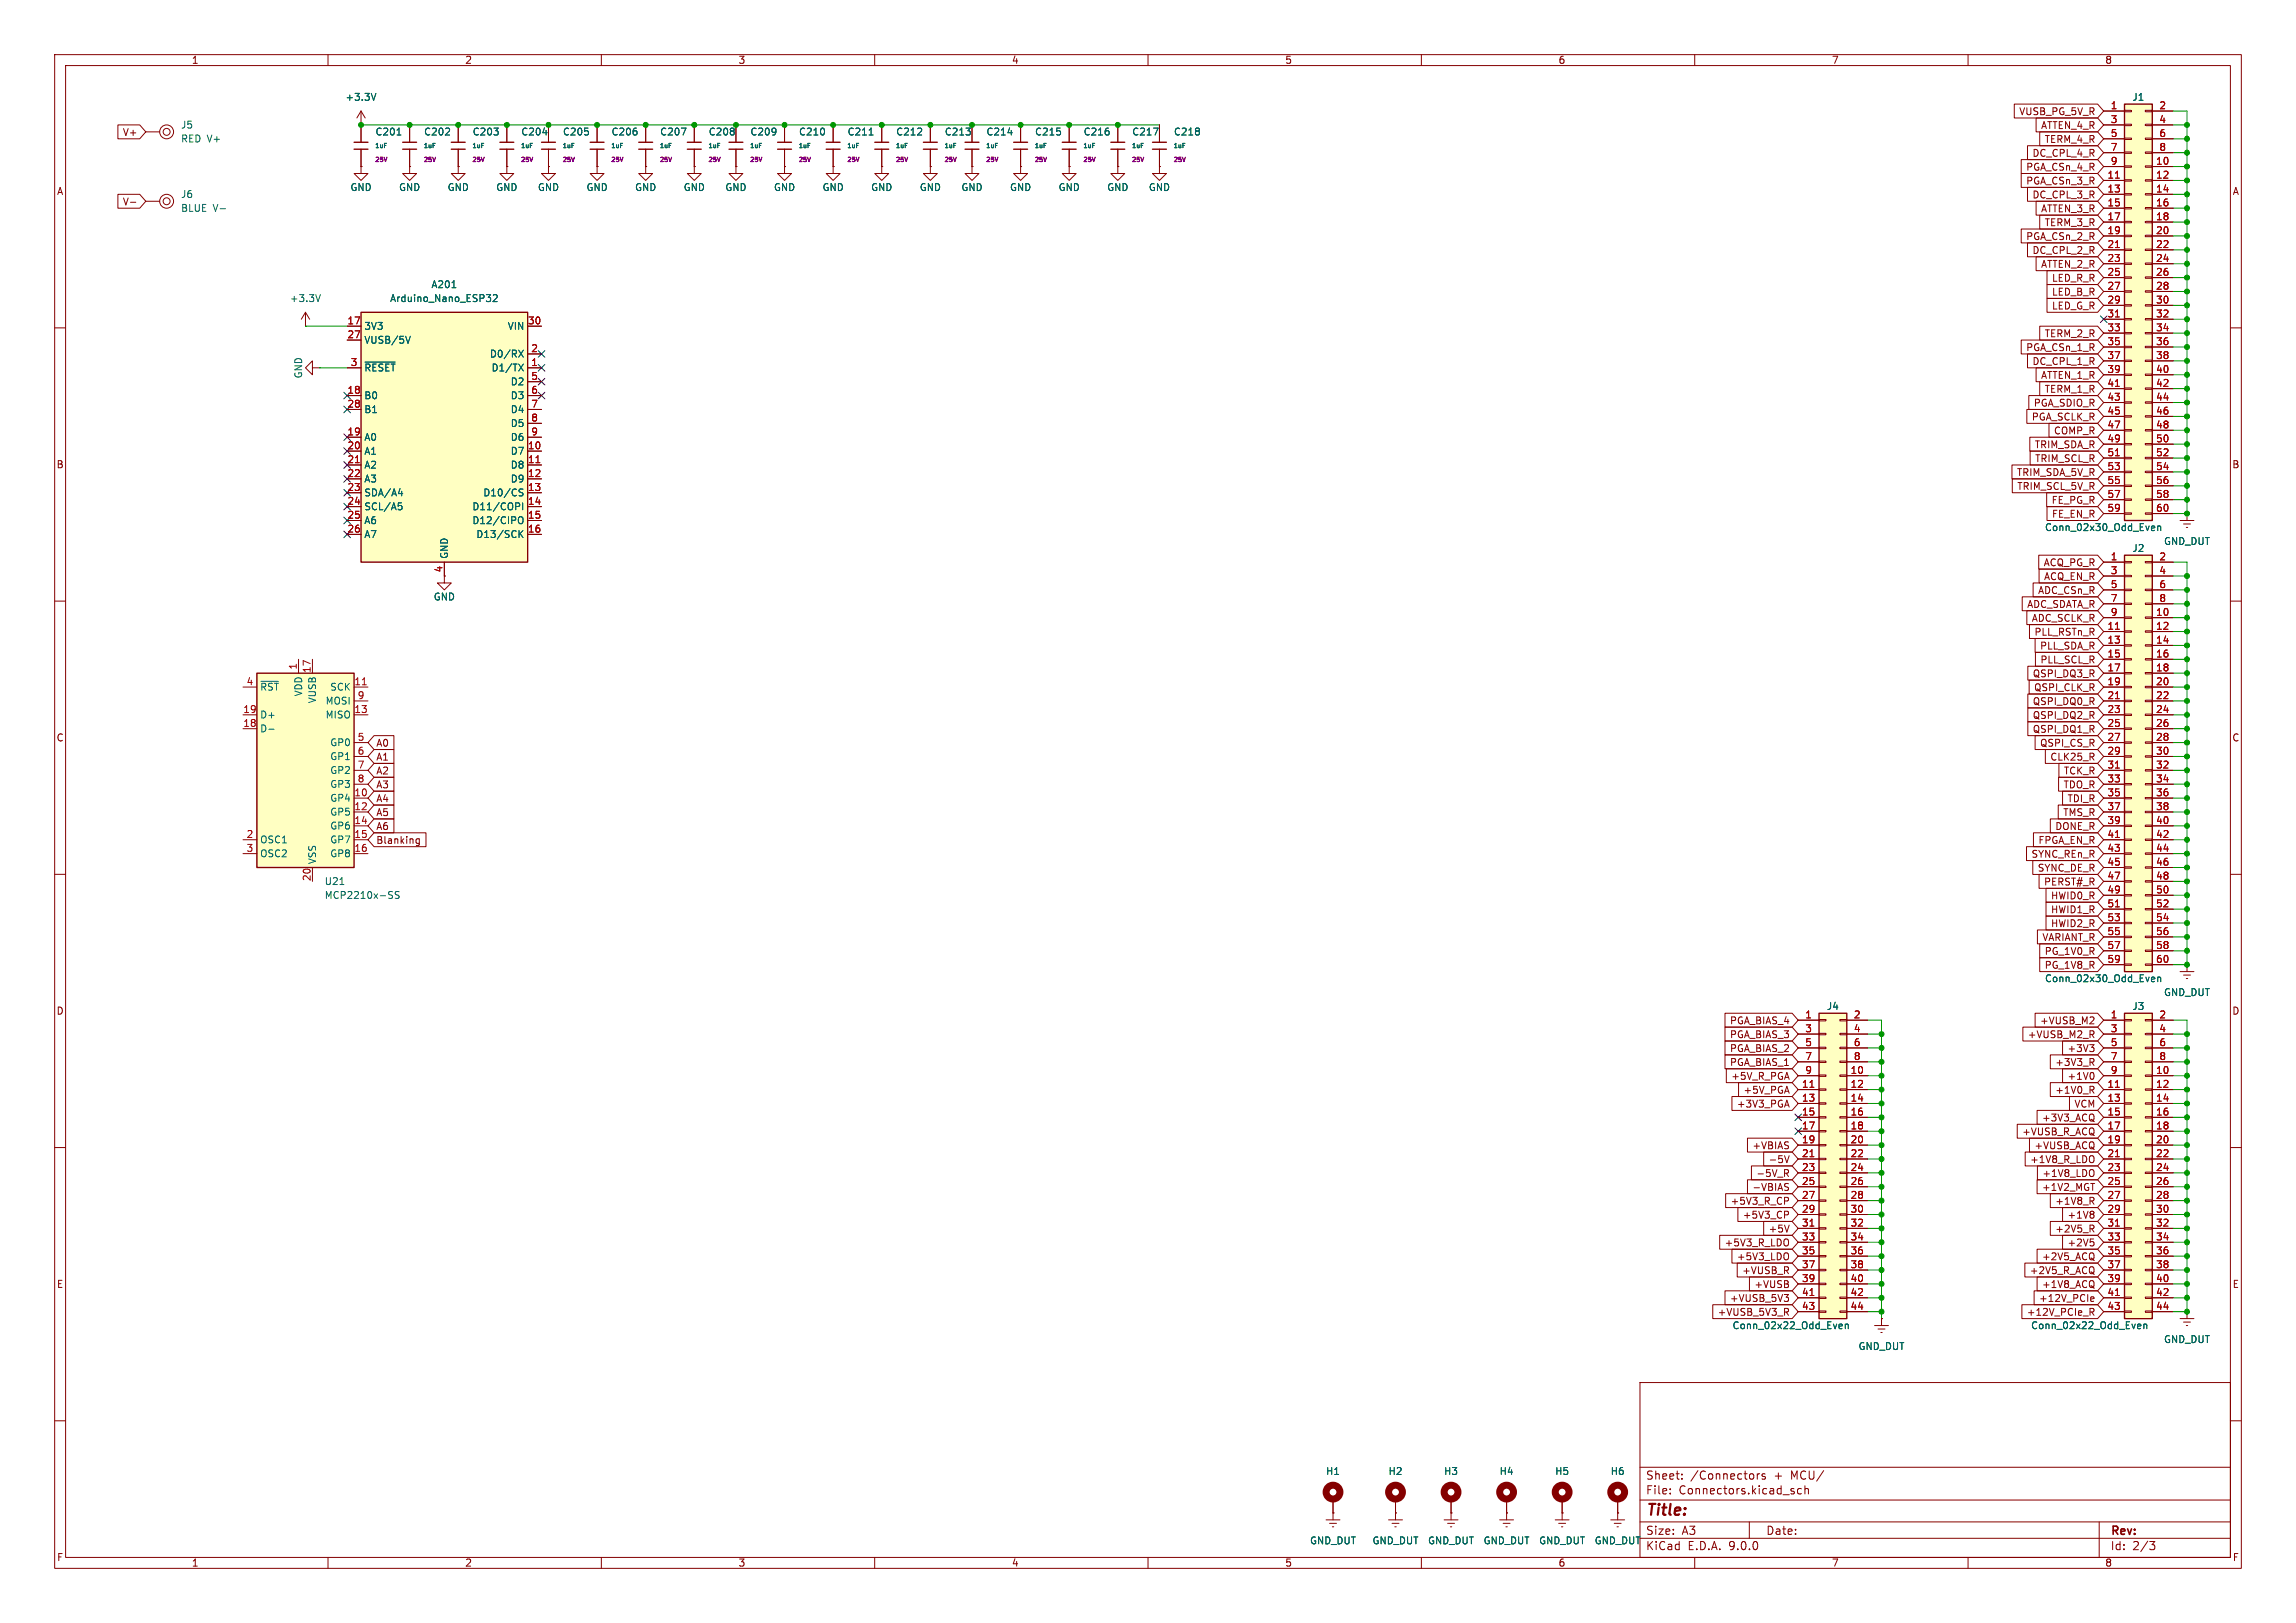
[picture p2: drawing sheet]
<svg xmlns="http://www.w3.org/2000/svg" width="420mm" height="297mm" viewBox="0 0 420 297" stroke-linecap="round" stroke-linejoin="round" font-family="sans-serif">
<defs><g id="words">
<text font-size="2.8" fill="#840000" x="301" y="277.9">Title:</text>
<g font-size="2.1" fill="#840000">
<text x="301" y="273.7">File:</text>
<text x="301" y="271">Sheet:</text>
<text x="307.1" y="273.7">Connectors.kicad_sch</text>
<text x="309.2" y="271">/Connectors</text>
<text x="324.6" y="271">+</text>
<text x="327.7" y="271">MCU/</text>
<text x="301" y="281.1">Size:</text>
<text x="307.6" y="281.1">A3</text>
<text x="323" y="281.1">Date:</text>
<text x="386" y="281.3">Rev:</text>
<text x="301" y="283.9">KiCad</text>
<text x="308.7" y="283.9">E.D.A.</text>
<text x="316.3" y="283.9">9.0.0</text>
<text x="386" y="283.9">Id:</text>
<text x="390.1" y="283.9">2/3</text>
</g>
<g font-size="1.8" fill="#840000">
<text x="35" y="11.9">1</text>
<text x="85" y="11.9">2</text>
<text x="135" y="11.9">3</text>
<text x="185" y="11.9">4</text>
<text x="235" y="11.9">5</text>
<text x="285" y="11.9">6</text>
<text x="335" y="11.9">7</text>
<text x="385" y="11.9">8</text>
<text x="369.3" y="21.3">VUSB_PG_5V_R</text>
<text x="373.3" y="23.8">ATTEN_4_R</text>
<text x="22.4" y="25.1">V+</text>
<text x="371.7" y="28.9">DC_CPL_4_R</text>
<text x="373.9" y="26.4">TERM_4_R</text>
<text x="10.3" y="35.9">A</text>
<text x="370.5" y="31.4">PGA_CSn_4_R</text>
<text x="370.5" y="34">PGA_CSn_3_R</text>
<text x="408.3" y="35.9">A</text>
<text x="22.4" y="37.8">V-</text>
<text x="371.7" y="36.5">DC_CPL_3_R</text>
<text x="373.3" y="39.1">ATTEN_3_R</text>
<text x="373.9" y="41.6">TERM_3_R</text>
<text x="370.5" y="44.1">PGA_CSn_2_R</text>
<text x="371.7" y="46.7">DC_CPL_2_R</text>
<text x="373.3" y="49.2">ATTEN_2_R</text>
<text x="375.3" y="51.8">LED_R_R</text>
<text x="375.3" y="56.8">LED_G_R</text>
<text x="375.3" y="54.3">LED_B_R</text>
<text x="370.5" y="64.5">PGA_CSn_1_R</text>
<text x="373.9" y="61.9">TERM_2_R</text>
<text x="371.7" y="67">DC_CPL_1_R</text>
<text x="373.3" y="69.5">ATTEN_1_R</text>
<text x="371.6" y="77.2">PGA_SCLK_R</text>
<text x="371.9" y="74.6">PGA_SDIO_R</text>
<text x="373.9" y="72.1">TERM_1_R</text>
<text x="372.1" y="82.2">TRIM_SDA_R</text>
<text x="375.6" y="79.7">COMP_R</text>
<text x="10.3" y="85.9">B</text>
<text x="368.8" y="87.3">TRIM_SDA_5V_R</text>
<text x="368.9" y="89.9">TRIM_SCL_5V_R</text>
<text x="372.2" y="84.8">TRIM_SCL_R</text>
<text x="408.2" y="85.9">B</text>
<text x="375.2" y="92.4">FE_PG_R</text>
<text x="375.3" y="94.9">FE_EN_R</text>
<text x="81" y="104.8" transform="rotate(-90 81 104.8)">4</text>
<text x="373.7" y="103.8">ACQ_PG_R</text>
<text x="373.8" y="106.4">ACQ_EN_R</text>
<text x="370.7" y="111.4">ADC_SDATA_R</text>
<text x="371.6" y="114">ADC_SCLK_R</text>
<text x="372.7" y="108.9">ADC_CSn_R</text>
<text x="372.1" y="116.5">PLL_RSTn_R</text>
<text x="373.1" y="119.1">PLL_SDA_R</text>
<text x="371.7" y="124.1">QSPI_DQ3_R</text>
<text x="373.1" y="121.6">PLL_SCL_R</text>
<text x="371.7" y="131.8">QSPI_DQ2_R</text>
<text x="371.7" y="129.2">QSPI_DQ0_R</text>
<text x="372" y="126.7">QSPI_CLK_R</text>
<text x="10.3" y="135.9">C</text>
<text x="68.7" y="136.8">A0</text>
<text x="371.7" y="134.3">QSPI_DQ1_R</text>
<text x="373.1" y="136.8">QSPI_CS_R</text>
<text x="408.2" y="135.9">C</text>
<text x="68.7" y="141.9">A2</text>
<text x="68.7" y="139.4">A1</text>
<text x="375" y="139.4">CLK25_R</text>
<text x="377.4" y="141.9">TCK_R</text>
<text x="68.7" y="144.5">A3</text>
<text x="68.7" y="147">A4</text>
<text x="68.7" y="149.5">A5</text>
<text x="377.3" y="149.5">TMS_R</text>
<text x="377.4" y="144.5">TDO_R</text>
<text x="378.1" y="147">TDI_R</text>
<text x="68.7" y="154.6">Blanking</text>
<text x="68.7" y="152.1">A6</text>
<text x="372.8" y="154.6">FPGA_EN_R</text>
<text x="375.9" y="152.1">DONE_R</text>
<text x="371.5" y="157.2">SYNC_REn_R</text>
<text x="372.7" y="159.7">SYNC_DE_R</text>
<text x="373.8" y="162.2">PERST#_R</text>
<text x="375.1" y="167.3">HWID1_R</text>
<text x="375.1" y="164.8">HWID0_R</text>
<text x="373.5" y="172.4">VARIANT_R</text>
<text x="375.1" y="169.9">HWID2_R</text>
<text x="373.9" y="174.9">PG_1V0_R</text>
<text x="373.9" y="177.5">PG_1V8_R</text>
<text x="10.3" y="185.9">D</text>
<text x="408.2" y="185.9">D</text>
<text x="316.4" y="187.6">PGA_BIAS_4</text>
<text x="316.4" y="190.2">PGA_BIAS_3</text>
<text x="370.8" y="190.2">+VUSB_M2_R</text>
<text x="373.1" y="187.6">+VUSB_M2</text>
<text x="316.4" y="192.7">PGA_BIAS_2</text>
<text x="316.4" y="195.3">PGA_BIAS_1</text>
<text x="316.6" y="197.8">+5V_R_PGA</text>
<text x="375.9" y="195.3">+3V3_R</text>
<text x="378.1" y="197.8">+1V0</text>
<text x="378.1" y="192.7">+3V3</text>
<text x="317.6" y="202.9">+3V3_PGA</text>
<text x="318.8" y="200.3">+5V_PGA</text>
<text x="375.9" y="200.3">+1V0_R</text>
<text x="379.4" y="202.9">VCM</text>
<text x="369.8" y="208">+VUSB_R_ACQ</text>
<text x="373.4" y="205.4">+3V3_ACQ</text>
<text x="320.5" y="210.5">+VBIAS</text>
<text x="321.2" y="215.6">-5V_R</text>
<text x="323.4" y="213">-5V</text>
<text x="371.3" y="213">+1V8_R_LDO</text>
<text x="372.1" y="210.5">+VUSB_ACQ</text>
<text x="373.5" y="215.6">+1V8_LDO</text>
<text x="316.5" y="220.7">+5V3_R_CP</text>
<text x="320.5" y="218.1">-VBIAS</text>
<text x="373.4" y="218.1">+1V2_MGT</text>
<text x="375.9" y="220.7">+1V8_R</text>
<text x="318.7" y="223.2">+5V3_CP</text>
<text x="323.4" y="225.7">+5V</text>
<text x="375.9" y="225.7">+2V5_R</text>
<text x="378.1" y="223.2">+1V8</text>
<text x="315.4" y="228.3">+5V3_R_LDO</text>
<text x="317.6" y="230.8">+5V3_LDO</text>
<text x="318.6" y="233.4">+VUSB_R</text>
<text x="371.2" y="233.4">+2V5_R_ACQ</text>
<text x="373.4" y="230.8">+2V5_ACQ</text>
<text x="378.1" y="228.3">+2V5</text>
<text x="10.3" y="235.9">E</text>
<text x="316.4" y="238.4">+VUSB_5V3</text>
<text x="320.8" y="235.9">+VUSB</text>
<text x="372.9" y="238.4">+12V_PCIe</text>
<text x="373.4" y="235.9">+1V8_ACQ</text>
<text x="408.3" y="235.9">E</text>
<text x="314.1" y="241">+VUSB_5V3_R</text>
<text x="370.7" y="241">+12V_PCIe_R</text>
<text x="10.3" y="285.9">F</text>
<text x="35" y="286.9">1</text>
<text x="85" y="286.9">2</text>
<text x="135" y="286.9">3</text>
<text x="185" y="286.9">4</text>
<text x="235" y="286.9">5</text>
<text x="285" y="286.9">6</text>
<text x="335" y="286.9">7</text>
<text x="385" y="286.9">8</text>
<text x="408.3" y="285.9">F</text>
</g>
<g font-size="1.8" fill="#006464">
<text x="33" y="23.7">J5</text>
<text x="63.1" y="18.6">+3.3V</text>
<text x="390" y="18.6">J1</text>
<text x="33" y="26.3">RED V+</text>
<text x="68.6" y="25">C201</text>
<text x="77.5" y="25">C202</text>
<text x="86.4" y="25">C203</text>
<text x="95.3" y="25">C204</text>
<text x="102.9" y="25">C205</text>
<text x="111.8" y="25">C206</text>
<text x="120.7" y="25">C207</text>
<text x="129.5" y="25">C208</text>
<text x="137.2" y="25">C209</text>
<text x="146.1" y="25">C210</text>
<text x="154.9" y="25">C211</text>
<text x="163.8" y="25">C212</text>
<text x="172.7" y="25">C213</text>
<text x="180.3" y="25">C214</text>
<text x="189.2" y="25">C215</text>
<text x="198.1" y="25">C216</text>
<text x="207" y="25">C217</text>
<text x="214.6" y="25">C218</text>
<text x="64" y="35.2">GND</text>
<text x="72.9" y="35.2">GND</text>
<text x="81.8" y="35.2">GND</text>
<text x="90.7" y="35.2">GND</text>
<text x="98.3" y="35.2">GND</text>
<text x="107.2" y="35.2">GND</text>
<text x="116.1" y="35.2">GND</text>
<text x="125" y="35.2">GND</text>
<text x="132.6" y="35.2">GND</text>
<text x="141.5" y="35.2">GND</text>
<text x="150.4" y="35.2">GND</text>
<text x="159.3" y="35.2">GND</text>
<text x="168.1" y="35.2">GND</text>
<text x="175.8" y="35.2">GND</text>
<text x="184.7" y="35.2">GND</text>
<text x="193.5" y="35.2">GND</text>
<text x="202.4" y="35.2">GND</text>
<text x="210.1" y="35.2">GND</text>
<text x="33" y="36.4">J6</text>
<text x="33" y="39">BLUE</text>
<text x="39" y="39">V-</text>
<text x="78.8" y="52.9">A201</text>
<text x="52.9" y="55.5">+3.3V</text>
<text x="71.3" y="55.5">Arduino_Nano_ESP32</text>
<text x="66.5" y="60.6">3V3</text>
<text x="66.5" y="63.1">VUSB/5V</text>
<text x="89.5" y="65.6">D0/RX</text>
<text x="92.8" y="60.6">VIN</text>
<text x="55.5" y="69.3" transform="rotate(-90 55.5 69.3)">GND</text>
<text x="66.5" y="68.2">~{RESET}</text>
<text x="89.8" y="68.2">D1/TX</text>
<text x="93.3" y="70.7">D2</text>
<text x="66.5" y="73.3">B0</text>
<text x="66.5" y="75.8">B1</text>
<text x="93.3" y="73.3">D3</text>
<text x="93.3" y="75.8">D4</text>
<text x="66.5" y="80.9">A0</text>
<text x="66.5" y="83.4">A1</text>
<text x="93.3" y="78.3">D5</text>
<text x="93.3" y="80.9">D6</text>
<text x="93.3" y="83.4">D7</text>
<text x="66.5" y="86">A2</text>
<text x="66.5" y="88.5">A3</text>
<text x="93.3" y="86">D8</text>
<text x="93.3" y="88.5">D9</text>
<text x="66.5" y="91">SDA/A4</text>
<text x="66.5" y="93.6">SCL/A5</text>
<text x="86.3" y="93.6">D11/COPI</text>
<text x="88.3" y="91">D10/CS</text>
<text x="66.5" y="96.1">A6</text>
<text x="66.5" y="98.7">A7</text>
<text x="86.3" y="96.1">D12/CIPO</text>
<text x="87" y="98.7">D13/SCK</text>
<text x="374" y="97.4">Conn_02x30_Odd_Even</text>
<text x="390" y="101.2">J2</text>
<text x="395.7" y="99.9">GND_DUT</text>
<text x="82.1" y="102.4" transform="rotate(-90 82.1 102.4)">GND</text>
<text x="79.2" y="110.1">GND</text>
<text x="47.5" y="126.6">~{RST}</text>
<text x="47.5" y="131.7">D+</text>
<text x="55.5" y="127.5" transform="rotate(-90 55.5 127.5)">VDD</text>
<text x="58" y="128.8" transform="rotate(-90 58 128.8)">VUSB</text>
<text x="59.5" y="129.1">MOSI</text>
<text x="59.5" y="131.7">MISO</text>
<text x="60.3" y="126.6">SCK</text>
<text x="47.5" y="134.2">D-</text>
<text x="60.3" y="136.8">GP0</text>
<text x="60.3" y="139.3">GP1</text>
<text x="60.3" y="141.8">GP2</text>
<text x="60.3" y="144.4">GP3</text>
<text x="60.3" y="146.9">GP4</text>
<text x="60.3" y="149.5">GP5</text>
<text x="47.5" y="154.5">OSC1</text>
<text x="60.3" y="152">GP6</text>
<text x="60.3" y="154.5">GP7</text>
<text x="47.5" y="157.1">OSC2</text>
<text x="58" y="158.2" transform="rotate(-90 58 158.2)">VSS</text>
<text x="60.3" y="157.1">GP8</text>
<text x="59.3" y="162.2">U21</text>
<text x="59.3" y="164.7">MCP2210x-SS</text>
<text x="374" y="179.9">Conn_02x30_Odd_Even</text>
<text x="334.1" y="185">J4</text>
<text x="390" y="185">J3</text>
<text x="395.7" y="182.5">GND_DUT</text>
<text x="316.8" y="243.4">Conn_02x22_Odd_Even</text>
<text x="371.4" y="243.4">Conn_02x22_Odd_Even</text>
<text x="395.7" y="246">GND_DUT</text>
<text x="339.9" y="247.2">GND_DUT</text>
<text x="242.5" y="270.1">H1</text>
<text x="253.9" y="270.1">H2</text>
<text x="264.1" y="270.1">H3</text>
<text x="274.2" y="270.1">H4</text>
<text x="284.4" y="270.1">H5</text>
<text x="294.5" y="270.1">H6</text>
<text x="239.5" y="282.8">GND_DUT</text>
<text x="251" y="282.8">GND_DUT</text>
<text x="261.1" y="282.8">GND_DUT</text>
<text x="271.3" y="282.8">GND_DUT</text>
<text x="281.4" y="282.8">GND_DUT</text>
<text x="291.6" y="282.8">GND_DUT</text>
</g>
<g font-size="1.8" fill="#a90000">
<text x="386" y="20.1">1</text>
<text x="386" y="22.6">3</text>
<text x="394.9" y="20.1">2</text>
<text x="394.9" y="22.6">4</text>
<text x="386" y="25.1">5</text>
<text x="386" y="27.7">7</text>
<text x="394.9" y="25.1">6</text>
<text x="394.9" y="27.7">8</text>
<text x="385.4" y="32.8">11</text>
<text x="385.4" y="35.3">13</text>
<text x="386" y="30.2">9</text>
<text x="394.3" y="30.2">10</text>
<text x="394.3" y="32.8">12</text>
<text x="394.3" y="35.3">14</text>
<text x="385.4" y="37.8">15</text>
<text x="385.4" y="40.4">17</text>
<text x="394.3" y="37.8">16</text>
<text x="394.3" y="40.4">18</text>
<text x="385.4" y="42.9">19</text>
<text x="385.4" y="45.5">21</text>
<text x="394.3" y="42.9">20</text>
<text x="394.3" y="45.5">22</text>
<text x="385.4" y="48">23</text>
<text x="385.4" y="50.5">25</text>
<text x="385.4" y="53.1">27</text>
<text x="394.3" y="48">24</text>
<text x="394.3" y="50.5">26</text>
<text x="394.3" y="53.1">28</text>
<text x="63.5" y="59.4">17</text>
<text x="96.5" y="59.4">30</text>
<text x="385.4" y="55.6">29</text>
<text x="385.4" y="58.2">31</text>
<text x="394.3" y="55.6">30</text>
<text x="394.3" y="58.2">32</text>
<text x="63.5" y="62">27</text>
<text x="97.1" y="64.5">2</text>
<text x="385.4" y="60.7">33</text>
<text x="385.4" y="63.2">35</text>
<text x="385.4" y="65.8">37</text>
<text x="394.3" y="60.7">34</text>
<text x="394.3" y="63.2">36</text>
<text x="394.3" y="65.8">38</text>
<text x="64.1" y="67.1">3</text>
<text x="97.1" y="67.1">1</text>
<text x="97.1" y="69.6">5</text>
<text x="385.4" y="68.3">39</text>
<text x="385.4" y="70.9">41</text>
<text x="394.3" y="68.3">40</text>
<text x="394.3" y="70.9">42</text>
<text x="63.5" y="72.1">18</text>
<text x="63.5" y="74.7">28</text>
<text x="97.1" y="72.1">6</text>
<text x="97.1" y="74.7">7</text>
<text x="97.1" y="77.2">8</text>
<text x="385.4" y="73.4">43</text>
<text x="385.4" y="75.9">45</text>
<text x="394.3" y="73.4">44</text>
<text x="394.3" y="75.9">46</text>
<text x="63.5" y="79.8">19</text>
<text x="63.5" y="82.3">20</text>
<text x="96.5" y="82.3">10</text>
<text x="97.1" y="79.8">9</text>
<text x="385.4" y="78.5">47</text>
<text x="385.4" y="81">49</text>
<text x="385.4" y="83.6">51</text>
<text x="394.3" y="78.5">48</text>
<text x="394.3" y="81">50</text>
<text x="394.3" y="83.6">52</text>
<text x="63.5" y="84.8">21</text>
<text x="63.5" y="87.4">22</text>
<text x="63.5" y="89.9">23</text>
<text x="96.5" y="84.8">11</text>
<text x="96.5" y="87.4">12</text>
<text x="96.5" y="89.9">13</text>
<text x="385.4" y="86.1">53</text>
<text x="385.4" y="88.6">55</text>
<text x="394.3" y="86.1">54</text>
<text x="394.3" y="88.6">56</text>
<text x="63.5" y="92.5">24</text>
<text x="63.5" y="95">25</text>
<text x="96.5" y="92.5">14</text>
<text x="96.5" y="95">15</text>
<text x="385.4" y="91.2">57</text>
<text x="385.4" y="93.7">59</text>
<text x="394.3" y="91.2">58</text>
<text x="394.3" y="93.7">60</text>
<text x="63.5" y="97.5">26</text>
<text x="96.5" y="97.5">16</text>
<text x="386" y="102.6">1</text>
<text x="386" y="105.2">3</text>
<text x="386" y="107.7">5</text>
<text x="394.9" y="102.6">2</text>
<text x="394.9" y="105.2">4</text>
<text x="394.9" y="107.7">6</text>
<text x="386" y="110.2">7</text>
<text x="386" y="112.8">9</text>
<text x="394.3" y="112.8">10</text>
<text x="394.9" y="110.2">8</text>
<text x="385.4" y="115.3">11</text>
<text x="385.4" y="117.9">13</text>
<text x="394.3" y="115.3">12</text>
<text x="394.3" y="117.9">14</text>
<text x="45" y="125.5">4</text>
<text x="54.4" y="122.6" transform="rotate(-90 54.4 122.6)">1</text>
<text x="56.9" y="123.2" transform="rotate(-90 56.9 123.2)">17</text>
<text x="64.7" y="125.5">11</text>
<text x="385.4" y="120.4">15</text>
<text x="385.4" y="122.9">17</text>
<text x="385.4" y="125.5">19</text>
<text x="394.3" y="120.4">16</text>
<text x="394.3" y="122.9">18</text>
<text x="394.3" y="125.5">20</text>
<text x="44.4" y="130.6">19</text>
<text x="64.7" y="130.6">13</text>
<text x="65.3" y="128">9</text>
<text x="385.4" y="128">21</text>
<text x="385.4" y="130.6">23</text>
<text x="394.3" y="128">22</text>
<text x="394.3" y="130.6">24</text>
<text x="44.4" y="133.1">18</text>
<text x="65.3" y="135.6">5</text>
<text x="385.4" y="133.1">25</text>
<text x="385.4" y="135.6">27</text>
<text x="394.3" y="133.1">26</text>
<text x="394.3" y="135.6">28</text>
<text x="65.3" y="138.2">6</text>
<text x="65.3" y="140.7">7</text>
<text x="65.3" y="143.3">8</text>
<text x="385.4" y="138.2">29</text>
<text x="385.4" y="140.7">31</text>
<text x="385.4" y="143.3">33</text>
<text x="394.3" y="138.2">30</text>
<text x="394.3" y="140.7">32</text>
<text x="394.3" y="143.3">34</text>
<text x="64.7" y="145.8">10</text>
<text x="64.7" y="148.3">12</text>
<text x="385.4" y="145.8">35</text>
<text x="385.4" y="148.3">37</text>
<text x="394.3" y="145.8">36</text>
<text x="394.3" y="148.3">38</text>
<text x="45" y="153.4">2</text>
<text x="45" y="156">3</text>
<text x="64.7" y="150.9">14</text>
<text x="64.7" y="153.4">15</text>
<text x="64.7" y="156">16</text>
<text x="385.4" y="150.9">39</text>
<text x="385.4" y="153.4">41</text>
<text x="385.4" y="156">43</text>
<text x="394.3" y="150.9">40</text>
<text x="394.3" y="153.4">42</text>
<text x="394.3" y="156">44</text>
<text x="56.9" y="161.3" transform="rotate(-90 56.9 161.3)">20</text>
<text x="385.4" y="158.5">45</text>
<text x="385.4" y="161">47</text>
<text x="394.3" y="158.5">46</text>
<text x="394.3" y="161">48</text>
<text x="385.4" y="163.6">49</text>
<text x="385.4" y="166.1">51</text>
<text x="394.3" y="163.6">50</text>
<text x="394.3" y="166.1">52</text>
<text x="385.4" y="168.7">53</text>
<text x="385.4" y="171.2">55</text>
<text x="385.4" y="173.7">57</text>
<text x="394.3" y="168.7">54</text>
<text x="394.3" y="171.2">56</text>
<text x="394.3" y="173.7">58</text>
<text x="385.4" y="176.3">59</text>
<text x="394.3" y="176.3">60</text>
<text x="330.1" y="186.4">1</text>
<text x="330.1" y="189">3</text>
<text x="330.1" y="191.5">5</text>
<text x="339" y="186.4">2</text>
<text x="339" y="189">4</text>
<text x="339" y="191.5">6</text>
<text x="386" y="186.4">1</text>
<text x="386" y="189">3</text>
<text x="386" y="191.5">5</text>
<text x="394.9" y="186.4">2</text>
<text x="394.9" y="189">4</text>
<text x="394.9" y="191.5">6</text>
<text x="330.1" y="194.1">7</text>
<text x="330.1" y="196.6">9</text>
<text x="338.4" y="196.6">10</text>
<text x="339" y="194.1">8</text>
<text x="386" y="194.1">7</text>
<text x="386" y="196.6">9</text>
<text x="394.3" y="196.6">10</text>
<text x="394.9" y="194.1">8</text>
<text x="329.5" y="199.1">11</text>
<text x="329.5" y="201.7">13</text>
<text x="338.4" y="199.1">12</text>
<text x="338.4" y="201.7">14</text>
<text x="385.4" y="199.1">11</text>
<text x="385.4" y="201.7">13</text>
<text x="394.3" y="199.1">12</text>
<text x="394.3" y="201.7">14</text>
<text x="329.5" y="204.2">15</text>
<text x="329.5" y="206.8">17</text>
<text x="329.5" y="209.3">19</text>
<text x="338.4" y="204.2">16</text>
<text x="338.4" y="206.8">18</text>
<text x="338.4" y="209.3">20</text>
<text x="385.4" y="204.2">15</text>
<text x="385.4" y="206.8">17</text>
<text x="385.4" y="209.3">19</text>
<text x="394.3" y="204.2">16</text>
<text x="394.3" y="206.8">18</text>
<text x="394.3" y="209.3">20</text>
<text x="329.5" y="211.8">21</text>
<text x="329.5" y="214.4">23</text>
<text x="338.4" y="211.8">22</text>
<text x="338.4" y="214.4">24</text>
<text x="385.4" y="211.8">21</text>
<text x="385.4" y="214.4">23</text>
<text x="394.3" y="211.8">22</text>
<text x="394.3" y="214.4">24</text>
<text x="329.5" y="216.9">25</text>
<text x="329.5" y="219.5">27</text>
<text x="329.5" y="222">29</text>
<text x="338.4" y="216.9">26</text>
<text x="338.4" y="219.5">28</text>
<text x="338.4" y="222">30</text>
<text x="385.4" y="216.9">25</text>
<text x="385.4" y="219.5">27</text>
<text x="385.4" y="222">29</text>
<text x="394.3" y="216.9">26</text>
<text x="394.3" y="219.5">28</text>
<text x="394.3" y="222">30</text>
<text x="329.5" y="224.5">31</text>
<text x="329.5" y="227.1">33</text>
<text x="338.4" y="224.5">32</text>
<text x="338.4" y="227.1">34</text>
<text x="385.4" y="224.5">31</text>
<text x="385.4" y="227.1">33</text>
<text x="394.3" y="224.5">32</text>
<text x="394.3" y="227.1">34</text>
<text x="329.5" y="229.6">35</text>
<text x="329.5" y="232.2">37</text>
<text x="338.4" y="229.6">36</text>
<text x="338.4" y="232.2">38</text>
<text x="385.4" y="229.6">35</text>
<text x="385.4" y="232.2">37</text>
<text x="394.3" y="229.6">36</text>
<text x="394.3" y="232.2">38</text>
<text x="329.5" y="234.7">39</text>
<text x="329.5" y="237.2">41</text>
<text x="329.5" y="239.8">43</text>
<text x="338.4" y="234.7">40</text>
<text x="338.4" y="237.2">42</text>
<text x="338.4" y="239.8">44</text>
<text x="385.4" y="234.7">39</text>
<text x="385.4" y="237.2">41</text>
<text x="385.4" y="239.8">43</text>
<text x="394.3" y="234.7">40</text>
<text x="394.3" y="237.2">42</text>
<text x="394.3" y="239.8">44</text>
</g>
<g font-size="1.1" fill="#840084">
<text x="68.5" y="29.8">25V</text>
<text x="77.4" y="29.8">25V</text>
<text x="86.3" y="29.8">25V</text>
<text x="95.2" y="29.8">25V</text>
<text x="102.8" y="29.8">25V</text>
<text x="111.7" y="29.8">25V</text>
<text x="120.6" y="29.8">25V</text>
<text x="129.5" y="29.8">25V</text>
<text x="137.1" y="29.8">25V</text>
<text x="146" y="29.8">25V</text>
<text x="154.9" y="29.8">25V</text>
<text x="163.8" y="29.8">25V</text>
<text x="172.6" y="29.8">25V</text>
<text x="180.3" y="29.8">25V</text>
<text x="189.2" y="29.8">25V</text>
<text x="198" y="29.8">25V</text>
<text x="206.9" y="29.8">25V</text>
<text x="214.6" y="29.8">25V</text>
</g>
<g font-size="1.1" fill="#006464">
<text x="68.5" y="27.3">1uF</text>
<text x="77.4" y="27.3">1uF</text>
<text x="86.3" y="27.3">1uF</text>
<text x="95.2" y="27.3">1uF</text>
<text x="102.8" y="27.3">1uF</text>
<text x="111.7" y="27.3">1uF</text>
<text x="120.6" y="27.3">1uF</text>
<text x="129.5" y="27.3">1uF</text>
<text x="137.1" y="27.3">1uF</text>
<text x="146" y="27.3">1uF</text>
<text x="154.9" y="27.3">1uF</text>
<text x="163.8" y="27.3">1uF</text>
<text x="172.6" y="27.3">1uF</text>
<text x="180.3" y="27.3">1uF</text>
<text x="189.2" y="27.3">1uF</text>
<text x="198" y="27.3">1uF</text>
<text x="206.9" y="27.3">1uF</text>
<text x="214.6" y="27.3">1uF</text>
</g>
</g></defs>
<g fill="none" stroke="#840000" stroke-width=".18">
<path d="M10 10h400v277h-400zM12 12h396v273h-396zM60 10v2M110 10v2M160 10v2M210 10v2M260 10v2M310 10v2M360 10v2M26.7 24.1h2.5M26.7 36.8h2.5M74.9 30.5v1.3h1.3l-1.3 1.2-1.2-1.2h1.2"/>
<path d="M74.9 30.5h.1M74.9 22.9v3.1M74.9 27.3v3.2M83.8 30.5v1.3h1.3l-1.3 1.2-1.3-1.2h1.3M83.8 30.5h.1M83.8 22.9v3.1M83.8 27.3v3.2M109.2 30.5v1.3h1.3l-1.3 1.2-1.3-1.2h1.3M109.2 30.5h.1M109.2 22.9v3.1M109.2 27.3v3.2M118.1 30.5v1.3h1.3l-1.3 1.2-1.3-1.2h1.3"/>
<path d="M118.1 30.5h.1M118.1 22.9v3.1M118.1 27.3v3.2M127 30.5v1.3h1.3l-1.3 1.2-1.3-1.2h1.3M127 30.5h.1M127 22.9v3.1M127 27.3v3.2M134.6 30.5v1.3h1.3l-1.3 1.2-1.3-1.2h1.3M134.6 30.5h.1M134.6 22.9v3.1M134.6 27.3v3.2M143.5 30.5v1.3h1.3l-1.3 1.2-1.3-1.2h1.3"/>
<path d="M143.5 30.5h.1M143.5 22.9v3.1M143.5 27.3v3.2M152.4 30.5v1.3h1.3l-1.3 1.2-1.3-1.2h1.3M152.4 30.5h.1M152.4 22.9v3.1M152.4 27.3v3.2M161.3 30.5v1.3h1.3l-1.3 1.2-1.3-1.2h1.3M161.3 30.5h.1M161.3 22.9v3.1M161.3 27.3v3.2M170.2 30.5v1.3h1.2l-1.2 1.2-1.3-1.2h1.3"/>
<path d="M170.2 30.5h.1M170.2 22.9v3.1M170.2 27.3v3.2M177.8 30.5v1.3h1.3l-1.3 1.2-1.3-1.2h1.3M177.8 30.5h.1M186.7 22.9v3.1M186.7 27.3v3.2M195.6 22.9v3.1M195.6 27.3v3.2M212.1 30.5v1.3h1.3l-1.3 1.2-1.3-1.2h1.3M212.1 30.5h.1M212.1 22.9v3.1"/>
<path d="M212.1 27.3v3.2M55.9 59.7h.1M55.9 57.2l.7 1.2M55.9 57.2l-.8 1.2M55.9 57.2v2.5M10 60h2M57.1 67.3v1.3l-1.2-1.3 1.2-1.3v1.3h1.3M58.4 67.3h.1M408 60h2M398.8 95.3h2.5M399.4 95.9h1.3M399.9 96.5h.3"/>
<path d="M400 94h.1M400 94v1.3M10 110h2M408 110h2M10 160h2M408 160h2M10 210h2M408 210h2M300 253h108v32h-108zM342.9 242.6h2.5M343.5 243.2h1.3M344 243.8h.3"/>
<path d="M344.2 241.3h.1M344.2 241.3v1.3M10 260h2M242.6 278.1h2.5M243.2 278.8h1.3M243.7 279.4h.3M243.8 276.9h.1M243.8 274.3v3.8M254 278.1h2.5M254.6 278.8h1.3M255.1 279.4h.3M255.3 276.9h.1"/>
<path d="M255.3 274.3v3.8M264.2 278.1h2.5M264.8 278.8h1.3M265.3 279.4h.3M265.4 276.9h.1M265.4 274.3v3.8M274.3 278.1h2.6M275 278.8h1.2M275.5 279.4h.2M275.6 276.9h.1M275.6 274.3v3.8M284.5 278.1h2.5"/>
<path d="M285.1 278.8h1.3M285.6 279.4h.3M285.7 276.9h.1M285.7 274.3v3.8M294.6 278.1h2.6M295.3 278.8h1.2M295.8 279.4h.2M295.9 276.9h.1M295.9 276.9v1.2M300 278.5h108M300 274.5h108M300 268.5h108"/>
<path d="M305.5 273.2v.2M305.5 272.5v.1M307.7 270.5v.2M307.7 269.8v.1M320 278.5v3M321.4 269.7v1M321.9 269.7l-.3 .1-.2 .2M322.9 269.8l-.4-.1-.2 .2 .1 .2 .5 .2v.3h-.6M328.2 273v.3M329.5 272.5l-.4-.1-.3 .3v.4l.1 .2h.6M330.2 272.5l.2-.1 .3 .1 .1 .9M330.2 271.9v1.5"/>
<path d="M384 278.5v6.5M408 260h2M60 285v2M110 285v2M160 285v2M210 285v2M260 285v2M300 281.5h108M310 285v2M360 285v2M393.2 282.1h1l-.5 .6 .4 .1 .1 .5-.3 .3h-.5"/>
<circle cx="30.5" cy="36.8" r=".63"/>
<circle cx="30.5" cy="24.1" r=".63"/>
<circle cx="30.5" cy="24.1" r="1.27"/>
<circle cx="30.5" cy="36.8" r="1.27"/>
</g>
<g fill="none" stroke="#840000" stroke-width="1.3">
<circle cx="243.8" cy="273" r="1.27"/>
<circle cx="255.3" cy="273" r="1.27"/>
<circle cx="265.4" cy="273" r="1.27"/>
<circle cx="275.6" cy="273" r="1.27"/>
<circle cx="285.8" cy="273" r="1.27"/>
</g>
<path d="M124.6 23.4h.9l-.6 1.3M159 24.7h.7M58.6 53.9l-.4 1.3" fill="none" stroke="#006464" stroke-width=".18"/>
<g fill="none" stroke="#840000" stroke-width=".25">
<path d="M73.7 26h2.5M73.7 27.3h2.5M82.5 26h2.6M82.5 27.3h2.6M107.9 26h2.6M107.9 27.3h2.6M116.8 26h2.6M116.8 27.3h2.6M125.7 26h2.6M125.7 27.3h2.6M133.3 26h2.6M133.3 27.3h2.6"/>
<path d="M142.2 26h2.6M142.2 27.3h2.6M151.1 26h2.6M151.1 27.3h2.6M160 26h2.6M160 27.3h2.6M168.9 26h2.5M168.9 27.3h2.5M185.4 26h2.6M185.4 27.3h2.6M194.3 26h2.5M194.3 27.3h2.5"/>
<path d="M210.8 26h2.6M210.8 27.3h2.6"/>
</g>
<path d="M332.7 185.4h5.1v55.9h-5.1z" fill="#ffffc2"/>
<path d="M332.7 185.4h5.1v55.9h-5.1z" fill="none" stroke="#840000" stroke-width=".25"/>
<g fill="none" stroke="#840000" stroke-width=".18">
<path d="M328.9 186.7h3.8M328.9 189.2h3.8M328.9 191.8h3.8M328.9 194.3h3.8M328.9 196.9h3.8M328.9 199.4h3.8M332.7 186.6h1.3v.2h-1.3zM332.7 189.1h1.3v.3h-1.3zM332.7 191.6h1.3v.3h-1.3zM332.7 194.2h1.3v.2h-1.3zM332.7 196.7h1.3v.3h-1.3zM332.7 199.3h1.3v.2h-1.3z"/>
<path d="M336.5 186.6h1.3v.2h-1.3zM336.5 189.1h1.3v.3h-1.3zM336.5 191.6h1.3v.3h-1.3zM336.5 194.2h1.3v.2h-1.3zM336.5 196.7h1.3v.3h-1.3zM336.5 199.3h1.3v.2h-1.3zM337.8 186.7h3.8M337.8 189.2h3.8M337.8 191.8h3.8M337.8 194.3h3.8M337.8 196.9h3.8M337.8 199.4h3.8"/>
<path d="M328.9 201.9h3.8M328.9 204.5h3.8M328.9 207h3.8M328.9 209.6h3.8M328.9 212.1h3.8M328.9 214.6h3.8M328.9 217.2h3.8M328.9 219.7h3.8M332.7 201.8h1.3v.3h-1.3zM332.7 204.3h1.3v.3h-1.3zM332.7 206.9h1.3v.2h-1.3zM332.7 209.4h1.3v.3h-1.3z"/>
<path d="M332.7 212h1.3v.2h-1.3zM332.7 214.5h1.3v.3h-1.3zM332.7 217h1.3v.3h-1.3zM332.7 219.6h1.3v.2h-1.3zM336.5 201.8h1.3v.3h-1.3zM336.5 204.3h1.3v.3h-1.3zM336.5 206.9h1.3v.2h-1.3zM336.5 209.4h1.3v.3h-1.3zM336.5 212h1.3v.2h-1.3zM336.5 214.5h1.3v.3h-1.3zM336.5 217h1.3v.3h-1.3zM336.5 219.6h1.3v.2h-1.3z"/>
<path d="M337.8 201.9h3.8M337.8 204.5h3.8M337.8 207h3.8M337.8 209.6h3.8M337.8 212.1h3.8M337.8 214.6h3.8M337.8 217.2h3.8M337.8 219.7h3.8M328.9 222.2h3.8M328.9 224.8h3.8M328.9 227.3h3.8M328.9 229.9h3.8"/>
<path d="M328.9 232.4h3.8M328.9 234.9h3.8M328.9 237.5h3.8M332.7 222.1h1.3v.3h-1.3zM332.7 224.7h1.3v.2h-1.3zM332.7 227.2h1.3v.3h-1.3zM332.7 229.7h1.3v.3h-1.3zM332.7 232.3h1.3v.2h-1.3zM332.7 234.8h1.3v.3h-1.3zM332.7 237.4h1.3v.2h-1.3zM332.7 239.9h1.3v.3h-1.3zM336.5 222.1h1.3v.3h-1.3z"/>
<path d="M336.5 224.7h1.3v.2h-1.3zM336.5 227.2h1.3v.3h-1.3zM336.5 229.7h1.3v.3h-1.3zM336.5 232.3h1.3v.2h-1.3zM336.5 234.8h1.3v.3h-1.3zM336.5 237.4h1.3v.2h-1.3zM336.5 239.9h1.3v.3h-1.3zM337.8 222.2h3.8M337.8 224.8h3.8M337.8 227.3h3.8M337.8 229.9h3.8M337.8 232.4h3.8"/>
<path d="M337.8 234.9h3.8M337.8 237.5h3.8M328.9 240h3.8M337.8 240h3.8"/>
</g>
<path d="M331.1 199h.7M331.1 211.7h.7M331.1 224.4h.7M331.1 237.1h.7" fill="none" stroke="#a90000" stroke-width=".18"/>
<path d="M336.6 242.3l.3 .1 .1 .2-.6 .1M336.9 243.1h-.3M337.5 242.4l.2-.1 .3 .1 .1 .7M337.5 242.3v.8" fill="none" stroke="#006464" stroke-width=".18"/>
<path d="M388.6 19.1h5.1v76.2h-5.1z" fill="#ffffc2"/>
<path d="M388.6 19.1h5.1v76.2h-5.1zM64.8 26h2.5M64.8 27.3h2.5M176.5 26h2.6M176.5 27.3h2.6M203.2 26h2.5M203.2 27.3h2.5" fill="none" stroke="#840000" stroke-width=".25"/>
<g fill="none" stroke="#840000" stroke-width=".18">
<path d="M66 30.5v1.3h1.3l-1.3 1.2-1.2-1.2h1.2M66 30.5h.1M66 22.9h.1M66 20.3v5.7M66 27.3v3.2M66 20.3l-.7 1.3M66 20.3l.8 1.3M177.8 22.9v3.1M177.8 27.3v3.2M186.7 30.5v1.3h1.3l-1.3 1.2-1.3-1.2h1.3M186.7 30.5h.1M195.6 30.5v1.3h1.2l-1.2 1.2-1.3-1.2h1.3"/>
<path d="M195.6 30.5h.1M204.5 30.5v1.3h1.2l-1.2 1.2-1.3-1.2h1.3M204.5 30.5h.1M204.5 22.9v3.1M204.5 27.3v3.2M384.8 20.3h3.8M384.8 22.9h3.8M384.8 25.4h3.8M384.8 27.9h3.8M384.8 30.5h3.8M384.8 33h3.8M384.8 35.6h3.8"/>
<path d="M384.8 38.1h3.8M388.6 20.2h1.3v.2h-1.3zM388.6 22.7h1.3v.3h-1.3zM388.6 25.3h1.3v.2h-1.3zM388.6 27.8h1.3v.3h-1.3zM388.6 30.4h1.3v.2h-1.3zM388.6 32.9h1.3v.2h-1.3zM388.6 35.4h1.3v.3h-1.3zM388.6 38h1.3v.2h-1.3zM392.4 20.2h1.3v.2h-1.3zM392.4 22.7h1.3v.3h-1.3zM392.4 25.3h1.3v.2h-1.3z"/>
<path d="M392.4 27.8h1.3v.3h-1.3zM392.4 30.4h1.3v.2h-1.3zM392.4 32.9h1.3v.2h-1.3zM392.4 35.4h1.3v.3h-1.3zM392.4 38h1.3v.2h-1.3zM393.7 20.3h3.8M393.7 22.9h3.8M393.7 25.4h3.8M393.7 27.9h3.8M393.7 30.5h3.8M393.7 33h3.8M393.7 35.6h3.8"/>
<path d="M393.7 38.1h3.8M384.8 40.6h3.8M384.8 43.2h3.8M384.8 45.7h3.8M384.8 48.3h3.8M384.8 50.8h3.8M384.8 53.3h3.8M384.8 55.9h3.8M384.8 58.4h3.8M388.6 40.5h1.3v.3h-1.3zM388.6 43.1h1.3v.2h-1.3zM388.6 45.6h1.3v.2h-1.3z"/>
<path d="M388.6 48.1h1.3v.3h-1.3zM388.6 50.7h1.3v.2h-1.3zM388.6 53.2h1.3v.3h-1.3zM388.6 55.8h1.3v.2h-1.3zM388.6 58.3h1.3v.2h-1.3zM392.4 40.5h1.3v.3h-1.3zM392.4 43.1h1.3v.2h-1.3zM392.4 45.6h1.3v.2h-1.3zM392.4 48.1h1.3v.3h-1.3zM392.4 50.7h1.3v.2h-1.3zM392.4 53.2h1.3v.3h-1.3zM392.4 55.8h1.3v.2h-1.3z"/>
<path d="M392.4 58.3h1.3v.2h-1.3zM393.7 40.6h3.8M393.7 43.2h3.8M393.7 45.7h3.8M393.7 48.3h3.8M393.7 50.8h3.8M393.7 53.3h3.8M393.7 55.9h3.8M393.7 58.4h3.8M384.8 61h3.8M384.8 63.5h3.8M384.8 66h3.8"/>
<path d="M384.8 68.6h3.8M384.8 71.1h3.8M384.8 73.7h3.8M384.8 76.2h3.8M384.8 78.7h3.8M388.6 60.8h1.3v.3h-1.3zM388.6 63.4h1.3v.2h-1.3zM388.6 65.9h1.3v.3h-1.3zM388.6 68.5h1.3v.2h-1.3zM388.6 71h1.3v.2h-1.3zM388.6 73.5h1.3v.3h-1.3zM388.6 76.1h1.3v.2h-1.3z"/>
<path d="M388.6 78.6h1.3v.3h-1.3zM392.4 60.8h1.3v.3h-1.3zM392.4 63.4h1.3v.2h-1.3zM392.4 65.9h1.3v.3h-1.3zM392.4 68.5h1.3v.2h-1.3zM392.4 71h1.3v.2h-1.3zM392.4 73.5h1.3v.3h-1.3zM392.4 76.1h1.3v.2h-1.3zM392.4 78.6h1.3v.3h-1.3zM393.7 61h3.8M393.7 63.5h3.8M393.7 66h3.8"/>
<path d="M393.7 68.6h3.8M393.7 71.1h3.8M393.7 73.7h3.8M393.7 76.2h3.8M393.7 78.7h3.8M384.8 81.3h3.8M384.8 83.8h3.8M384.8 86.4h3.8M384.8 88.9h3.8M384.8 91.4h3.8M384.8 94h3.8M388.6 81.2h1.3v.2h-1.3z"/>
<path d="M388.6 83.7h1.3v.2h-1.3zM388.6 86.2h1.3v.3h-1.3zM388.6 88.8h1.3v.2h-1.3zM388.6 91.3h1.3v.3h-1.3zM388.6 93.9h1.3v.2h-1.3zM392.4 81.2h1.3v.2h-1.3zM392.4 83.7h1.3v.2h-1.3zM392.4 86.2h1.3v.3h-1.3zM392.4 88.8h1.3v.2h-1.3zM392.4 91.3h1.3v.3h-1.3zM392.4 93.9h1.3v.2h-1.3zM393.7 81.3h3.8"/>
<path d="M393.7 83.8h3.8M393.7 86.4h3.8M393.7 88.9h3.8M393.7 91.4h3.8M393.7 94h3.8M81.3 105.4v1.3h-1.3l1.3 1.3 1.2-1.3h-1.2M398.8 177.8h2.5M399.4 178.4h1.3M399.9 179.1h.3M400 176.5h.1M400 176.5v1.3"/>
</g>
<path d="M387 32.6h.7M387 45.3h.7M387 58h.7M387 70.7h.7M387 83.4h.7" fill="none" stroke="#a90000" stroke-width=".18"/>
<path d="M68.8 17.1l-.5 1.3M72.6 24.7h.7M184.4 24.3h.8M211 23.4h.8l-.5 1.3M393.7 96.3h.4l.1 .3-.7 .1M394.1 97l-.4 .1M394.7 96.4l.2-.1h.3v.8M394.7 96.3v.8" fill="none" stroke="#006464" stroke-width=".18"/>
<path d="M66 57.2h30.5v45.7h-30.5z" fill="#ffffc2"/>
<path d="M66 57.2h30.5v45.7h-30.5z" fill="none" stroke="#840000" stroke-width=".25"/>
<g fill="none" stroke="#840000" stroke-width=".18">
<path d="M63.5 59.7h2.5M96.5 59.7h2.6M63.5 67.3h2.5M63.5 72.4h2.5M63.5 74.9h2.5M63.5 62.2h2.5M96.5 64.8h2.6M96.5 67.3h2.6M96.5 69.9h2.6M96.5 72.4h2.6M96.5 74.9h2.6M96.5 77.5h2.6"/>
<path d="M63.5 80h2.5M63.5 82.6h2.5M63.5 85.1h2.5M63.5 87.6h2.5M63.5 90.2h2.5M63.5 92.7h2.5M63.5 95.3h2.5M63.5 97.8h2.5M96.5 80h2.6M96.5 82.6h2.6M96.5 85.1h2.6M96.5 87.6h2.6"/>
<path d="M96.5 90.2h2.6M96.5 92.7h2.6M96.5 95.3h2.6M96.5 97.8h2.6M81.3 102.9v2.5"/>
</g>
<g fill="none" stroke="#006464" stroke-width=".18">
<path d="M82.7 52.6h.7M89 53.9h.7l-.4 .5M89.5 54.4l.2 .2v.3l-.2 .3M90.2 54l.5-.1 .3 .4-.8 .9h.8M66.8 66.3h5.5M74.2 61.5l.4 1.3 .5-1.3M94.9 64.1l.8 1.2M94.9 66.6l.8 1.3M95.7 64.1l-.8 1.2M95.7 66.6l-.8 1.3M72.9 92h.6M72.9 90.3h.8"/>
<path d="M73 92.5h.3l.2 .2v.5l-.5 .1M73.5 89.9v.8M94.8 92l.3 .3-.1 .3-.2 .1M94.9 94.7l.2-.1a.43 .43 0 0 1 .6 .4v.4a.43 .43 0 0 1-.3 .4 .43 .43 0 0 1-.5-.2M95 90l.5 .2 .2 .3-.3 .2h-.5M95.1 97.6l.6 .8M95.6 92v1.3M95.7 97.1l-.8 .7M95.7 89.5h-.5l-.2 .1"/>
</g>
<path d="M65 84.7h.7M98 84.7h.8" fill="none" stroke="#a90000" stroke-width=".18"/>
<path d="M47 123.2h17.8v35.6h-17.8z" fill="#ffffc2"/>
<path d="M91.4 26h2.6M91.4 27.3h2.6M99.1 26h2.5M99.1 27.3h2.5M47 123.2h17.8v35.6h-17.8z" fill="none" stroke="#840000" stroke-width=".25"/>
<g fill="none" stroke="#840000" stroke-width=".18">
<path d="M92.7 30.5v1.3h1.3l-1.3 1.2-1.3-1.2h1.3M92.7 30.5h.1M92.7 22.9v3.1M92.7 27.3v3.2M100.3 30.5v1.3h1.3l-1.3 1.2-1.2-1.2h1.2M100.3 30.5h.1M100.3 22.9v3.1M100.3 27.3v3.2M44.4 125.7h2.6M44.4 130.8h2.6M44.4 133.4h2.6M54.6 120.7v2.5"/>
<path d="M57.1 120.7v2.5M64.8 125.7h2.5M64.8 130.8h2.5M64.8 128.3h2.5M64.8 135.9h2.5M64.8 138.4h2.5M44.4 153.7h2.6M44.4 156.2h2.6M57.1 158.8v2.5M64.8 153.7h2.5M64.8 156.2h2.5M64.8 141h2.5"/>
<path d="M64.8 143.5h2.5M64.8 146.1h2.5M64.8 148.6h2.5M64.8 151.1h2.5M398.8 241.3h2.5M399.4 241.9h1.3M399.9 242.6h.3M400 240h.1M400 240v1.3"/>
</g>
<path d="M99.3 24.3h.8M47.7 124.7h3.2M49.2 133.4h.9M62.2 161.9h.7M71.3 163.7l.4 .2 .1 .3-.2 .2h-.3M71.3 163.1l.5 .1M73 163.2l-.5-.1-.2 .2v.3l.6 .3 .1 .3-.2 .2-.5-.1" fill="none" stroke="#006464" stroke-width=".18"/>
<path d="M66.3 125.3h.7" fill="none" stroke="#a90000" stroke-width=".18"/>
<path d="M388.6 101.6h5.1v76.2h-5.1z" fill="#ffffc2"/>
<path d="M388.6 101.6h5.1v76.2h-5.1z" fill="none" stroke="#840000" stroke-width=".25"/>
<g fill="none" stroke="#840000" stroke-width=".18">
<path d="M384.8 102.9h3.8M384.8 105.4h3.8M384.8 108h3.8M384.8 110.5h3.8M384.8 113h3.8M384.8 115.6h3.8M384.8 118.1h3.8M388.6 102.7h1.3v.3h-1.3zM388.6 105.3h1.3v.2h-1.3zM388.6 107.8h1.3v.3h-1.3zM388.6 110.4h1.3v.2h-1.3zM388.6 112.9h1.3v.3h-1.3z"/>
<path d="M388.6 115.4h1.3v.3h-1.3zM388.6 118h1.3v.2h-1.3zM392.4 102.7h1.3v.3h-1.3zM392.4 105.3h1.3v.2h-1.3zM392.4 107.8h1.3v.3h-1.3zM392.4 110.4h1.3v.2h-1.3zM392.4 112.9h1.3v.3h-1.3zM392.4 115.4h1.3v.3h-1.3zM392.4 118h1.3v.2h-1.3zM393.7 102.9h3.8M393.7 105.4h3.8M393.7 108h3.8"/>
<path d="M393.7 110.5h3.8M393.7 113h3.8M393.7 115.6h3.8M393.7 118.1h3.8M384.8 120.7h3.8M384.8 123.2h3.8M384.8 125.7h3.8M384.8 128.3h3.8M384.8 130.8h3.8M384.8 133.4h3.8M384.8 135.9h3.8M384.8 138.4h3.8"/>
<path d="M388.6 120.5h1.3v.3h-1.3zM388.6 123.1h1.3v.2h-1.3zM388.6 125.6h1.3v.3h-1.3zM388.6 128.1h1.3v.3h-1.3zM388.6 130.7h1.3v.2h-1.3zM388.6 133.2h1.3v.3h-1.3zM388.6 135.8h1.3v.2h-1.3zM388.6 138.3h1.3v.3h-1.3zM392.4 120.5h1.3v.3h-1.3zM392.4 123.1h1.3v.2h-1.3zM392.4 125.6h1.3v.3h-1.3zM392.4 128.1h1.3v.3h-1.3z"/>
<path d="M392.4 130.7h1.3v.2h-1.3zM392.4 133.2h1.3v.3h-1.3zM392.4 135.8h1.3v.2h-1.3zM392.4 138.3h1.3v.3h-1.3zM393.7 120.7h3.8M393.7 123.2h3.8M393.7 125.7h3.8M393.7 128.3h3.8M393.7 130.8h3.8M393.7 133.4h3.8M393.7 135.9h3.8M393.7 138.4h3.8"/>
<path d="M384.8 141h3.8M384.8 143.5h3.8M384.8 146.1h3.8M384.8 148.6h3.8M384.8 151.1h3.8M384.8 153.7h3.8M384.8 156.2h3.8M384.8 158.8h3.8M388.6 140.8h1.3v.3h-1.3zM388.6 143.4h1.3v.2h-1.3zM388.6 145.9h1.3v.3h-1.3zM388.6 148.5h1.3v.2h-1.3z"/>
<path d="M388.6 151h1.3v.3h-1.3zM388.6 153.5h1.3v.3h-1.3zM388.6 156.1h1.3v.2h-1.3zM388.6 158.6h1.3v.3h-1.3zM392.4 140.8h1.3v.3h-1.3zM392.4 143.4h1.3v.2h-1.3zM392.4 145.9h1.3v.3h-1.3zM392.4 148.5h1.3v.2h-1.3zM392.4 151h1.3v.3h-1.3zM392.4 153.5h1.3v.3h-1.3zM392.4 156.1h1.3v.2h-1.3zM392.4 158.6h1.3v.3h-1.3z"/>
<path d="M393.7 141h3.8M393.7 143.5h3.8M393.7 146.1h3.8M393.7 148.6h3.8M393.7 151.1h3.8M393.7 153.7h3.8M393.7 156.2h3.8M393.7 158.8h3.8M384.8 161.3h3.8M384.8 163.8h3.8M384.8 166.4h3.8M384.8 168.9h3.8"/>
<path d="M384.8 171.5h3.8M384.8 174h3.8M384.8 176.5h3.8M388.6 161.2h1.3v.2h-1.3zM388.6 163.7h1.3v.3h-1.3zM388.6 166.2h1.3v.3h-1.3zM388.6 168.8h1.3v.2h-1.3zM388.6 171.3h1.3v.3h-1.3zM388.6 173.9h1.3v.2h-1.3zM388.6 176.4h1.3v.3h-1.3zM392.4 161.2h1.3v.2h-1.3zM392.4 163.7h1.3v.3h-1.3z"/>
<path d="M392.4 166.2h1.3v.3h-1.3zM392.4 168.8h1.3v.2h-1.3zM392.4 171.3h1.3v.3h-1.3zM392.4 173.9h1.3v.2h-1.3zM392.4 176.4h1.3v.3h-1.3zM393.7 161.3h3.8M393.7 163.8h3.8M393.7 166.4h3.8M393.7 168.9h3.8M393.7 171.5h3.8M393.7 174h3.8M393.7 176.5h3.8"/>
</g>
<path d="M387 115.2h.7M387 127.9h.7M387 140.6h.7M387 153.3h.7M387 166h.7" fill="none" stroke="#a90000" stroke-width=".18"/>
<path d="M393.7 178.8l.4 .1 .1 .2-.7 .1M394.1 179.6h-.4M394.7 178.9l.2-.1 .3 .1v.7M394.7 178.8v.8" fill="none" stroke="#006464" stroke-width=".18"/>
<path d="M388.6 185.4h5.1v55.9h-5.1z" fill="#ffffc2"/>
<path d="M388.6 185.4h5.1v55.9h-5.1z" fill="none" stroke="#840000" stroke-width=".25"/>
<g fill="none" stroke="#840000" stroke-width=".18">
<path d="M368.5 19h15.2l1.1 1.3-1.1 1.3h-15.2zM21.6 22.9h4l1.1 1.2-1.1 1.3h-4zM21.6 35.6h4l1.1 1.2-1.1 1.3h-4zM23.9 37h.9M66 30.5h.1M66 22.9h.1M66 22.9v3.1M66 27.3v3.2M74.9 30.5h.1M74.9 22.9v3.1M74.9 27.3v3.2M83.8 30.5h.1"/>
<path d="M83.8 22.9v3.1M83.8 27.3v3.2M92.7 30.5h.1M92.7 22.9v3.1M92.7 27.3v3.2M100.3 30.5h.1M100.3 22.9v3.1M100.3 27.3v3.2M109.2 30.5h.1M109.2 22.9v3.1M109.2 27.3v3.2M118.1 30.5h.1"/>
<path d="M118.1 22.9v3.1M118.1 27.3v3.2M127 30.5h.1M127 22.9v3.1M127 27.3v3.2M134.6 30.5h.1M134.6 22.9v3.1M134.6 27.3v3.2M143.5 30.5h.1M143.5 22.9v3.1M143.5 27.3v3.2M152.4 30.5h.1"/>
<path d="M152.4 22.9v3.1M152.4 27.3v3.2M161.3 30.5h.1M161.3 22.9v3.1M161.3 27.3v3.2M170.2 30.5h.1M170.2 22.9v3.1M170.2 27.3v3.2M177.8 30.5h.1M177.8 22.9v3.1M177.8 27.3v3.2M186.7 30.5h.1"/>
<path d="M186.7 22.9v3.1M186.7 27.3v3.2M195.6 30.5h.1M195.6 22.9v3.1M195.6 27.3v3.2M204.5 30.5h.1M204.5 22.9v3.1M204.5 27.3v3.2M212.1 30.5h.1M212.1 22.9v3.1M212.1 27.3v3.2M369.7 29.2h14l1.1 1.3-1.1 1.3h-14z"/>
<path d="M369.7 31.7h14l1.1 1.3-1.1 1.3h-14zM370.9 26.7h12.8l1.1 1.2-1.1 1.3h-12.8zM370.9 34.3h12.8l1.1 1.3-1.1 1.2h-12.8zM372.4 21.6h11.3l1.1 1.3-1.1 1.2h-11.3zM372.4 36.8h11.3l1.1 1.3-1.1 1.3h-11.3zM373.1 39.4h10.6l1.1 1.2-1.1 1.3h-10.6zM373.1 24.1h10.6l1.1 1.3-1.1 1.3h-10.6zM384.8 20.3h3.8M384.8 22.9h3.8M384.8 25.4h3.8M384.8 27.9h3.8M384.8 30.5h3.8"/>
<path d="M384.8 33h3.8M384.8 35.6h3.8M384.8 38.1h3.8M393.7 20.3h3.8M393.7 22.9h3.8M393.7 25.4h3.8M393.7 27.9h3.8M393.7 30.5h3.8M393.7 33h3.8M393.7 35.6h3.8M393.7 38.1h3.8M63.5 59.7h2.5"/>
<path d="M96.5 59.7h2.6M369.7 41.9h14l1.1 1.3-1.1 1.3h-14zM370.9 44.4h12.8l1.1 1.3-1.1 1.3h-12.8zM372.4 47h11.3l1.1 1.3-1.1 1.2h-11.3zM373.1 59.7h10.6l1.1 1.3-1.1 1.2h-10.6zM374.4 49.5h9.3l1.1 1.3-1.1 1.3h-9.3zM374.4 54.6h9.3l1.1 1.3-1.1 1.3h-9.3zM374.4 52.1h9.3l1.1 1.2-1.1 1.3h-9.3zM384.8 40.6h3.8M384.8 43.2h3.8M384.8 45.7h3.8M384.8 48.3h3.8"/>
<path d="M384.8 50.8h3.8M384.8 53.3h3.8M384.8 55.9h3.8M384.8 58.4h3.8M393.7 40.6h3.8M393.7 43.2h3.8M393.7 45.7h3.8M393.7 48.3h3.8M393.7 50.8h3.8M393.7 53.3h3.8M393.7 55.9h3.8M393.7 58.4h3.8"/>
<path d="M63.5 67.3h2.5M63.5 72.4h2.5M63.5 74.9h2.5M63.5 62.2h2.5M96.5 64.8h2.6M96.5 67.3h2.6M96.5 69.9h2.6M96.5 72.4h2.6M96.5 74.9h2.6M96.5 77.5h2.6M369.7 62.2h14l1.1 1.3-1.1 1.3h-14zM370.8 74.9h12.9l1.1 1.3-1.1 1.3h-12.9z"/>
<path d="M370.9 64.8h12.8l1.1 1.2-1.1 1.3h-12.8zM371.1 72.4h12.6l1.1 1.3-1.1 1.2h-12.6zM372.4 67.3h11.3l1.1 1.3-1.1 1.3h-11.3zM373.1 69.8h10.6l1.1 1.3-1.1 1.3h-10.6zM374.8 77.5h8.9l1.1 1.2-1.1 1.3h-8.9zM384.8 61h3.8M384.8 63.5h3.8M384.8 66h3.8M384.8 68.6h3.8M384.8 71.1h3.8M384.8 73.7h3.8M384.8 76.2h3.8"/>
<path d="M384.8 78.7h3.8M393.7 61h3.8M393.7 63.5h3.8M393.7 66h3.8M393.7 68.6h3.8M393.7 71.1h3.8M393.7 73.7h3.8M393.7 76.2h3.8M393.7 78.7h3.8M63.5 80h2.5M63.5 82.6h2.5M63.5 85.1h2.5"/>
<path d="M63.5 87.6h2.5M63.5 90.2h2.5M63.5 92.7h2.5M63.5 95.3h2.5M63.5 97.8h2.5M96.5 80h2.6M96.5 82.6h2.6M96.5 85.1h2.6M96.5 87.6h2.6M96.5 90.2h2.6M96.5 92.7h2.6M96.5 95.3h2.6"/>
<path d="M96.5 97.8h2.6M368 85.1h15.7l1.1 1.3-1.1 1.2h-15.7zM368.1 87.6h15.6l1.1 1.3-1.1 1.3h-15.6zM371.3 80h12.4l1.1 1.3-1.1 1.3h-12.4zM371.4 82.5h12.3l1.1 1.3-1.1 1.3h-12.3zM374.4 90.2h9.3l1.1 1.2-1.1 1.3h-9.3zM374.4 92.7h9.3l1.1 1.3-1.1 1.3h-9.3zM384.8 81.3h3.8M384.8 83.8h3.8M384.8 86.4h3.8M384.8 88.9h3.8M384.8 91.4h3.8"/>
<path d="M384.8 94h3.8M393.7 81.3h3.8M393.7 83.8h3.8M393.7 86.4h3.8M393.7 88.9h3.8M393.7 91.4h3.8M393.7 94h3.8M400 94h.1M81.3 102.9v2.5M369.9 109.2h13.8l1.1 1.3-1.1 1.3h-13.8zM370.8 111.8h12.9l1.1 1.2-1.1 1.3h-12.9zM371.2 114.3h12.5l1.1 1.3-1.1 1.2h-12.5z"/>
<path d="M371.9 106.7h11.8l1.1 1.3-1.1 1.2h-11.8zM372.3 116.8h11.4l1.1 1.3-1.1 1.3h-11.4zM372.3 119.4h11.4l1.1 1.3-1.1 1.2h-11.4zM372.9 101.6h10.8l1.1 1.3-1.1 1.2h-10.8zM373 104.1h10.7l1.1 1.3-1.1 1.3h-10.7zM384.8 102.9h3.8M384.8 105.4h3.8M384.8 108h3.8M384.8 110.5h3.8M384.8 113h3.8M384.8 115.6h3.8M384.8 118.1h3.8"/>
<path d="M393.7 102.9h3.8M393.7 105.4h3.8M393.7 108h3.8M393.7 110.5h3.8M393.7 113h3.8M393.7 115.6h3.8M393.7 118.1h3.8M68.4 139.7h3.7v2.5h-3.7l-1.1-1.2zM68.4 137.2h3.7v2.5h-3.7l-1.1-1.3zM68.4 134.6h3.7v2.6h-3.7l-1.1-1.3zM370.9 129.5h12.8l1.1 1.3-1.1 1.3h-12.8zM370.9 127h12.8l1.1 1.3-1.1 1.2h-12.8z"/>
<path d="M370.9 121.9h12.8l1.1 1.3-1.1 1.3h-12.8zM370.9 132.1h12.8l1.1 1.3-1.1 1.2h-12.8zM371.2 124.5h12.5l1.1 1.2-1.1 1.3h-12.5zM372.3 134.6h11.4l1.1 1.3-1.1 1.3h-11.4zM374.1 137.2h9.6l1.1 1.2-1.1 1.3h-9.6zM376.6 139.7h7.1l1.1 1.3-1.1 1.2h-7.1zM384.8 120.7h3.8M384.8 123.2h3.8M384.8 125.7h3.8M384.8 128.3h3.8M384.8 130.8h3.8M384.8 133.4h3.8"/>
<path d="M384.8 135.9h3.8M384.8 138.4h3.8M393.7 120.7h3.8M393.7 123.2h3.8M393.7 125.7h3.8M393.7 128.3h3.8M393.7 130.8h3.8M393.7 133.4h3.8M393.7 135.9h3.8M393.7 138.4h3.8M68.4 142.2h3.7v2.6h-3.7l-1.1-1.3zM68.4 152.4h9.5v2.5h-9.5l-1.1-1.2z"/>
<path d="M68.4 149.9h3.7v2.5h-3.7l-1.1-1.3zM68.4 144.8h3.7v2.5h-3.7l-1.1-1.2zM68.4 147.3h3.7v2.6h-3.7l-1.1-1.3zM76.7 153.5v1l-.2 .3-.3-.1M76.7 153.6l-.4-.1-.2 .2 .1 .6h.5M370.7 154.9h13l1.1 1.3-1.1 1.3h-13zM371.8 157.5h11.9l1.1 1.3-1.1 1.2h-11.9zM372 152.4h11.7l1.1 1.3-1.1 1.2h-11.7zM375 149.9h8.7l1.1 1.2-1.1 1.3h-8.7zM376.5 147.3h7.2l1.1 1.3-1.1 1.3h-7.2zM376.6 142.2h7.1l1.1 1.3-1.1 1.3h-7.1zM377.3 144.8h6.4l1.1 1.3-1.1 1.2h-6.4z"/>
<path d="M384.8 141h3.8M384.8 143.5h3.8M384.8 146.1h3.8M384.8 148.6h3.8M384.8 151.1h3.8M384.8 153.7h3.8M384.8 156.2h3.8M384.8 158.8h3.8M393.7 141h3.8M393.7 143.5h3.8M393.7 146.1h3.8M393.7 148.6h3.8"/>
<path d="M393.7 151.1h3.8M393.7 153.7h3.8M393.7 156.2h3.8M393.7 158.8h3.8M372.7 170.2h11l1.1 1.3-1.1 1.2h-11zM373 160h10.7l1.1 1.3-1.1 1.3h-10.7zM373.1 172.7h10.6l1.1 1.3-1.1 1.3h-10.6zM373.1 175.3h10.6l1.1 1.2-1.1 1.3h-10.6zM374.3 165.1h9.4l1.1 1.3-1.1 1.2h-9.4zM374.3 162.6h9.4l1.1 1.2-1.1 1.3h-9.4zM374.3 167.6h9.4l1.1 1.3-1.1 1.3h-9.4zM384.8 161.3h3.8"/>
<path d="M384.8 163.8h3.8M384.8 166.4h3.8M384.8 168.9h3.8M384.8 171.5h3.8M384.8 174h3.8M384.8 176.5h3.8M393.7 161.3h3.8M393.7 163.8h3.8M393.7 166.4h3.8M393.7 168.9h3.8M393.7 171.5h3.8M393.7 174h3.8"/>
<path d="M393.7 176.5h3.8M400 176.5h.1M315.5 185.4h12.3l1.1 1.3-1.1 1.3h-12.3zM315.5 190.5h12.3l1.1 1.3-1.1 1.2h-12.3zM315.5 188h12.3l1.1 1.2-1.1 1.3h-12.3zM315.5 193h12.3l1.1 1.3-1.1 1.3h-12.3zM315.8 195.6h12l1.1 1.3-1.1 1.2h-12zM318 198.1h9.8l1.1 1.3-1.1 1.3h-9.8zM328.9 186.7h3.8M328.9 189.2h3.8M328.9 191.8h3.8M328.9 194.3h3.8"/>
<path d="M328.9 196.9h3.8M328.9 199.4h3.8M337.8 186.7h3.8M337.8 189.2h3.8M337.8 191.8h3.8M337.8 194.3h3.8M337.8 196.9h3.8M337.8 199.4h3.8M370 188h13.7l1.1 1.2-1.1 1.3h-13.7zM372.3 185.4h11.4l1.1 1.3-1.1 1.3h-11.4zM375 198.1h8.7l1.1 1.3-1.1 1.3h-8.7zM375 193h8.7l1.1 1.3-1.1 1.3h-8.7z"/>
<path d="M377.3 195.6h6.4l1.1 1.3-1.1 1.2h-6.4zM377.3 190.5h6.4l1.1 1.3-1.1 1.2h-6.4zM382.3 191.2h.7l-.4 .5M382.6 199.5l.4 .6M382.6 189.3l.4 .6M382.6 194.4l.4 .6M382.7 196.3a.79 .79 0 0 1 0 1.2M382.8 193.7l.2 .3v.3l-.2 .1M382.8 198.8l.2 .2v.3l-.2 .2M382.8 186.1l.2 .2v.3l-.7 .8h.7M382.8 191.7l.2 .2v.3l-.2 .2M382.9 188.7l.1 .2-.1 .3"/>
<path d="M384.8 186.7h3.8M384.8 189.2h3.8M384.8 191.8h3.8M384.8 194.3h3.8M384.8 196.9h3.8M384.8 199.4h3.8M388.6 186.6h1.3v.2h-1.3zM388.6 189.1h1.3v.3h-1.3zM388.6 191.6h1.3v.3h-1.3zM388.6 194.2h1.3v.2h-1.3zM388.6 196.7h1.3v.3h-1.3zM388.6 199.3h1.3v.2h-1.3z"/>
<path d="M392.4 186.6h1.3v.2h-1.3zM392.4 189.1h1.3v.3h-1.3zM392.4 191.6h1.3v.3h-1.3zM392.4 194.2h1.3v.2h-1.3zM392.4 196.7h1.3v.3h-1.3zM392.4 199.3h1.3v.2h-1.3zM393.7 186.7h3.8M393.7 189.2h3.8M393.7 191.8h3.8M393.7 194.3h3.8M393.7 196.9h3.8M393.7 199.4h3.8"/>
<path d="M315.7 218.4h12.1l1.1 1.3-1.1 1.3h-12.1zM316.8 200.7h11l1.1 1.2-1.1 1.3h-11zM319.7 208.3h8.1l1.1 1.3-1.1 1.2h-8.1zM319.7 215.9h8.1l1.1 1.3-1.1 1.2h-8.1zM320.4 213.4h7.4l1.1 1.2-1.1 1.3h-7.4zM322.6 210.8h5.2l1.1 1.3-1.1 1.3h-5.2zM326.4 214h.5l.3 .3-.2 .3-.6 .1M326.4 219.1h.5l.3 .3-.2 .3-.6 .1M326.4 211.5l.5 1.3 .4-1.3M326.6 202.2h.6M326.7 216.6h.5M326.7 217.2l.3 .1 .2 .3-.3 .2h-.3"/>
<path d="M326.7 214.7l.5 .6M326.9 201.3l.4 1.3M328.9 201.9h3.8M328.9 204.5h3.8M328.9 207h3.8M328.9 209.6h3.8M328.9 212.1h3.8M328.9 214.6h3.8M328.9 217.2h3.8M328.9 219.7h3.8M337.8 201.9h3.8M337.8 204.5h3.8"/>
<path d="M337.8 207h3.8M337.8 209.6h3.8M337.8 212.1h3.8M337.8 214.6h3.8M337.8 217.2h3.8M337.8 219.7h3.8M369 205.7h14.7l1.1 1.3-1.1 1.3h-14.7zM370.5 210.8h13.2l1.1 1.3-1.1 1.3h-13.2zM371.2 208.3h12.5l1.1 1.3-1.1 1.2h-12.5zM372.6 203.2h11.1l1.1 1.3-1.1 1.2h-11.1zM372.6 215.9h11.1l1.1 1.3-1.1 1.2h-11.1zM372.7 213.4h11l1.1 1.2-1.1 1.3h-11z"/>
<path d="M375 218.4h8.7l1.1 1.3-1.1 1.3h-8.7zM378.6 200.7h5.1l1.1 1.2-1.1 1.3h-5.1zM382.4 216.6h.8M382.6 219.8l.4 .6M382.7 214l.2 .1a.81 .81 0 0 1-.2 1.2M382.8 219.1l.2 .3v.3l-.2 .1M382.9 211.6a.9 .9 0 0 1 0 1.1M383 204.1v.9M383 205.2l.1 .1M384.8 201.9h3.8M384.8 204.5h3.8M384.8 207h3.8"/>
<path d="M384.8 209.6h3.8M384.8 212.1h3.8M384.8 214.6h3.8M384.8 217.2h3.8M384.8 219.7h3.8M388.6 201.8h1.3v.3h-1.3zM388.6 204.3h1.3v.3h-1.3zM388.6 206.9h1.3v.2h-1.3zM388.6 209.4h1.3v.3h-1.3zM388.6 212h1.3v.2h-1.3zM388.6 214.5h1.3v.3h-1.3zM388.6 217h1.3v.3h-1.3z"/>
<path d="M388.6 219.6h1.3v.2h-1.3zM392.4 201.8h1.3v.3h-1.3zM392.4 204.3h1.3v.3h-1.3zM392.4 206.9h1.3v.2h-1.3zM392.4 209.4h1.3v.3h-1.3zM392.4 212h1.3v.2h-1.3zM392.4 214.5h1.3v.3h-1.3zM392.4 217h1.3v.3h-1.3zM392.4 219.6h1.3v.2h-1.3zM393.7 201.9h3.8M393.7 204.5h3.8M393.7 207h3.8"/>
<path d="M393.7 209.6h3.8M393.7 212.1h3.8M393.7 214.6h3.8M393.7 217.2h3.8M393.7 219.7h3.8M313.3 238.8h14.5l1.1 1.2-1.1 1.3h-14.5zM314.6 226.1h13.2l1.1 1.2-1.1 1.3h-13.2zM315.5 236.2h12.3l1.1 1.3-1.1 1.3h-12.3zM316.8 228.6h11l1.1 1.3-1.1 1.2h-11zM317.8 231.1h10l1.1 1.3-1.1 1.3h-10zM317.9 221h9.9l1.1 1.2-1.1 1.3h-9.9zM320 233.7h7.8l1.1 1.2-1.1 1.3h-7.8z"/>
<path d="M322.6 223.5h5.2l1.1 1.3-1.1 1.3h-5.2zM326.4 236.9h.8l-.5 .5 .4 .1 .1 .4-.3 .3h-.3M326.4 239.4h.5l.3 .3-.2 .3-.6 .1M326.4 221.7h.5l.3 .2-.2 .4h-.6M326.9 229.3h.1a.81 .81 0 0 1-.1 1.2M327 226.8a.9 .9 0 0 1 0 1.1M327.3 224.2l-.4 1.3M328.9 222.2h3.8M328.9 224.8h3.8M328.9 227.3h3.8M328.9 229.9h3.8M328.9 232.4h3.8"/>
<path d="M328.9 234.9h3.8M328.9 237.5h3.8M337.8 222.2h3.8M337.8 224.8h3.8M337.8 227.3h3.8M337.8 229.9h3.8M337.8 232.4h3.8M337.8 234.9h3.8M337.8 237.5h3.8M369.8 238.8h13.9l1.1 1.2-1.1 1.3h-13.9zM370.4 231.1h13.3l1.1 1.3-1.1 1.3h-13.3zM372.1 236.2h11.6l1.1 1.3-1.1 1.3h-11.6z"/>
<path d="M372.6 228.6h11.1l1.1 1.3-1.1 1.2h-11.1zM372.6 233.7h11.1l1.1 1.2-1.1 1.3h-11.1zM375 223.5h8.7l1.1 1.3-1.1 1.3h-8.7zM377.3 226.1h6.4l1.1 1.2-1.1 1.3h-6.4zM377.3 221h6.4l1.1 1.2-1.1 1.3h-6.4zM382.3 239.4h.5l.2 .3-.1 .3-.6 .1M382.4 226.7h.6M382.5 237.4l.4-.1 .1 .3-.6 .1M382.5 238.1h.5M382.6 224.9l.4 .6M382.8 224.2l.2 .2v.3l-.2 .2M382.8 221.7l.2 .2-.2 .3 .2 .2v.3l-.2 .2"/>
<path d="M382.8 227.2l.2 .3v.3l-.2 .2M383 230.6l.1 .1M383 229.5v.9M383 232v.9M383 234.5v.9M383 233.1l.1 .1M383 235.7h.1M384.8 222.2h3.8M384.8 224.8h3.8M384.8 227.3h3.8M384.8 229.9h3.8M384.8 232.4h3.8"/>
<path d="M384.8 234.9h3.8M384.8 237.5h3.8M388.6 222.1h1.3v.3h-1.3zM388.6 224.7h1.3v.2h-1.3zM388.6 227.2h1.3v.3h-1.3zM388.6 229.7h1.3v.3h-1.3zM388.6 232.3h1.3v.2h-1.3zM388.6 234.8h1.3v.3h-1.3zM388.6 237.4h1.3v.2h-1.3zM388.6 239.9h1.3v.3h-1.3zM392.4 222.1h1.3v.3h-1.3zM392.4 224.7h1.3v.2h-1.3z"/>
<path d="M392.4 227.2h1.3v.3h-1.3zM392.4 229.7h1.3v.3h-1.3zM392.4 232.3h1.3v.2h-1.3zM392.4 234.8h1.3v.3h-1.3zM392.4 237.4h1.3v.2h-1.3zM392.4 239.9h1.3v.3h-1.3zM393.7 222.2h3.8M393.7 224.8h3.8M393.7 227.3h3.8M393.7 229.9h3.8M393.7 232.4h3.8M393.7 234.9h3.8"/>
<path d="M393.7 237.5h3.8M326.7 240.1l.5 .6M328.9 240h3.8M337.8 240h3.8M344.2 241.3h.1M382.6 240.1l.4 .6M384.8 240h3.8M393.7 240h3.8M400 240h.1M243.8 276.9h.1M243.8 274.3v2.6M255.3 276.9h.1"/>
<path d="M255.3 274.3v2.6M265.4 276.9h.1M265.4 274.3v2.6M275.6 276.9h.1M275.6 274.3v2.6M285.7 276.9h.1M285.7 274.3v2.6M295.9 276.9h.1M295.9 274.3v2.6"/>
</g>
<g fill="none" stroke="#a90000" stroke-width=".18">
<path d="M387 32.6h.7M387 45.3h.7M387 58h.7M387 70.7h.7M65 84.7h.7M98 84.7h.8M387 83.4h.7M387 115.2h.7M387 127.9h.7M387 140.6h.7M387 153.3h.7M387 166h.7"/>
<path d="M331.1 199h.7M387 199h.7M331.1 211.7h.7M387 211.7h.7M331.1 224.4h.7M331.1 237.1h.7M387 224.4h.7M387 237.1h.7"/>
</g>
<g fill="none" stroke="#006464" stroke-width=".18">
<path d="M68.8 17.1l-.5 1.3M72.6 24.7h.7M99.3 24.3h.8M124.6 23.4h.9l-.6 1.3M159 24.7h.7M184.4 24.3h.8M211 23.4h.8l-.5 1.3M82.7 52.6h.7M89 53.9h.7l-.4 .5M89.5 54.4l.2 .2v.3l-.2 .3M90.2 54l.5-.1 .3 .4-.8 .9h.8M66.8 66.3h5.5"/>
<path d="M74.2 61.5l.4 1.3 .5-1.3M94.9 64.1l.8 1.2M94.9 66.6l.8 1.3M95.7 64.1l-.8 1.2M95.7 66.6l-.8 1.3M72.9 92h.6M72.9 90.3h.8M73 92.5h.3l.2 .2v.5l-.5 .1M73.5 89.9v.8M94.8 92l.3 .3-.1 .3-.2 .1M94.9 94.7l.2-.1a.43 .43 0 0 1 .6 .4v.4a.43 .43 0 0 1-.3 .4 .43 .43 0 0 1-.5-.2M95 90l.5 .2 .2 .3-.3 .2h-.5"/>
<path d="M95.1 97.6l.6 .8M95.6 92v1.3M95.7 97.1l-.8 .7M95.7 89.5h-.5l-.2 .1M393.7 96.3h.4l.1 .3-.7 .1M394.1 97l-.4 .1M394.7 96.3v.8M394.7 96.4l.2-.1h.3v.8M393.7 178.8l.4 .1 .1 .2-.7 .1M394.1 179.6h-.4M394.7 178.9l.2-.1 .3 .1v.7M394.7 178.8v.8"/>
<path d="M336.6 242.3l.3 .1 .1 .2-.6 .1M336.9 243.1h-.3M337.5 242.4l.2-.1 .3 .1 .1 .7M337.5 242.3v.8M391.2 242.3l.4 .1v.2l-.6 .1M391.6 243.1h-.4M392.2 242.4l.1-.1 .3 .1 .1 .7M392.2 242.3v.8"/>
</g>
<circle cx="295.9" cy="273" r="1.27" fill="none" stroke="#840000" stroke-width="1.3"/>
<g fill="none" stroke="#009600" stroke-width=".18">
<path d="M66 22.9h146.1M397.5 20.3h2.5v73.7h-2.5M397.5 22.9h2.5M397.5 25.4h2.5M397.5 27.9h2.5M397.5 38.1h2.5M397.5 33h2.5M397.5 30.5h2.5M397.5 35.6h2.5M55.9 59.7h7.6M397.5 53.3h2.5M397.5 55.9h2.5"/>
<path d="M397.5 58.4h2.5M397.5 50.8h2.5M397.5 45.7h2.5M397.5 48.3h2.5M397.5 40.6h2.5M397.5 43.2h2.5M58.4 67.3h5.1M397.5 61h2.5M397.5 63.5h2.5M397.5 66h2.5M397.5 68.6h2.5M397.5 71.1h2.5"/>
<path d="M397.5 73.7h2.5M397.5 76.2h2.5M397.5 78.7h2.5M397.5 88.9h2.5M397.5 91.4h2.5M397.5 86.4h2.5M397.5 83.8h2.5M397.5 81.3h2.5M397.5 102.9h2.5v73.6h-2.5M397.5 105.4h2.5M397.5 108h2.5M397.5 115.6h2.5"/>
<path d="M397.5 113h2.5M397.5 118.1h2.5M397.5 110.5h2.5M397.5 133.4h2.5M397.5 135.9h2.5M397.5 130.8h2.5M397.5 128.3h2.5M397.5 123.2h2.5M397.5 125.7h2.5M397.5 138.4h2.5M397.5 120.7h2.5M397.5 141h2.5"/>
<path d="M397.5 151.1h2.5M397.5 156.2h2.5M397.5 158.8h2.5M397.5 153.7h2.5M397.5 146.1h2.5M397.5 143.5h2.5M397.5 148.6h2.5M397.5 171.5h2.5M397.5 174h2.5M397.5 168.9h2.5M397.5 161.3h2.5M397.5 166.4h2.5"/>
<path d="M397.5 163.8h2.5M341.6 186.7h2.6v54.6M341.6 199.4h2.6M341.6 189.2h2.6M341.6 191.8h2.6M341.6 194.3h2.6M341.6 196.9h2.6M397.5 199.4h2.5M397.5 186.7h2.5v53.3h-2.5M397.5 189.2h2.5M397.5 191.8h2.5M397.5 194.3h2.5"/>
<path d="M397.5 196.9h2.5M341.6 204.5h2.6M341.6 207h2.6M341.6 201.9h2.6M341.6 214.6h2.6M341.6 212.1h2.6M341.6 217.2h2.6M341.6 219.7h2.6M341.6 209.6h2.6M397.5 204.5h2.5M397.5 207h2.5M397.5 201.9h2.5"/>
<path d="M397.5 214.6h2.5M397.5 212.1h2.5M397.5 217.2h2.5M397.5 219.7h2.5M397.5 209.6h2.5M341.6 227.3h2.6M341.6 224.8h2.6M341.6 237.5h2.6M341.6 232.4h2.6M341.6 229.9h2.6M341.6 234.9h2.6M341.6 222.2h2.6"/>
<path d="M397.5 227.3h2.5M397.5 224.8h2.5M397.5 237.5h2.5M397.5 232.4h2.5M397.5 229.9h2.5M397.5 234.9h2.5M397.5 222.2h2.5M341.6 240h2.6"/>
</g>
<g fill="none" stroke="#000084" stroke-width=".18">
<path d="M384.2 57.8l1.2 1.2M385.4 57.8l-1.2 1.2M62.9 71.8l1.2 1.2M62.9 79.4l1.2 1.2M62.9 74.3l1.2 1.2M64.1 71.8l-1.2 1.2M64.1 79.4l-1.2 1.2M64.1 74.3l-1.2 1.2M98.5 71.8l1.2 1.2M98.5 64.2l1.2 1.2M98.5 66.7l1.2 1.2M98.5 69.2l1.2 1.3"/>
<path d="M99.7 71.8l-1.2 1.2M99.7 64.2l-1.2 1.2M99.7 66.7l-1.2 1.2M99.7 69.2l-1.2 1.3M62.9 89.6l1.2 1.2M62.9 87l1.2 1.2M62.9 92.1l1.2 1.2M62.9 94.6l1.2 1.3M62.9 84.5l1.2 1.2M62.9 97.2l1.2 1.2M62.9 81.9l1.2 1.3M64.1 89.6l-1.2 1.2"/>
<path d="M64.1 87l-1.2 1.2M64.1 92.1l-1.2 1.2M64.1 94.6l-1.2 1.3M64.1 84.5l-1.2 1.2M64.1 97.2l-1.2 1.2M64.1 81.9l-1.2 1.3M328.3 206.4l1.2 1.2M328.3 203.9l1.2 1.2M329.5 206.4l-1.2 1.2M329.5 203.9l-1.2 1.2"/>
</g>
<g fill="#009600" stroke="#009600" stroke-width=".18">
<circle cx="400" cy="128.3" r=".46"/>
<circle cx="400" cy="133.4" r=".46"/>
<circle cx="400" cy="120.7" r=".46"/>
<circle cx="400" cy="123.2" r=".46"/>
<circle cx="400" cy="125.7" r=".46"/>
<circle cx="400" cy="130.8" r=".46"/>
<circle cx="400" cy="135.9" r=".46"/>
<circle cx="400" cy="161.3" r=".46"/>
<circle cx="400" cy="158.8" r=".46"/>
<circle cx="400" cy="163.8" r=".46"/>
<circle cx="400" cy="166.4" r=".46"/>
<circle cx="400" cy="105.4" r=".46"/>
<circle cx="400" cy="88.9" r=".46"/>
<circle cx="400" cy="91.4" r=".46"/>
<circle cx="400" cy="94" r=".46"/>
<circle cx="400" cy="148.6" r=".46"/>
<circle cx="400" cy="143.5" r=".46"/>
<circle cx="400" cy="138.4" r=".46"/>
<circle cx="400" cy="151.1" r=".46"/>
<circle cx="400" cy="153.7" r=".46"/>
<circle cx="400" cy="146.1" r=".46"/>
<circle cx="400" cy="156.2" r=".46"/>
<circle cx="400" cy="141" r=".46"/>
<circle cx="400" cy="118.1" r=".46"/>
<circle cx="400" cy="110.5" r=".46"/>
<circle cx="400" cy="108" r=".46"/>
<circle cx="400" cy="113" r=".46"/>
<circle cx="400" cy="115.6" r=".46"/>
<circle cx="400" cy="78.7" r=".46"/>
<circle cx="400" cy="81.3" r=".46"/>
<circle cx="400" cy="83.8" r=".46"/>
<circle cx="400" cy="86.4" r=".46"/>
<circle cx="400" cy="168.9" r=".46"/>
<circle cx="400" cy="174" r=".46"/>
<circle cx="400" cy="171.5" r=".46"/>
<circle cx="400" cy="176.5" r=".46"/>
<circle cx="400" cy="71.1" r=".46"/>
<circle cx="400" cy="73.7" r=".46"/>
<circle cx="400" cy="76.2" r=".46"/>
<circle cx="74.9" cy="22.9" r=".46"/>
<circle cx="66" cy="22.9" r=".46"/>
<circle cx="92.7" cy="22.9" r=".46"/>
<circle cx="100.3" cy="22.9" r=".46"/>
<circle cx="83.8" cy="22.9" r=".46"/>
<circle cx="400" cy="27.9" r=".46"/>
<circle cx="400" cy="38.1" r=".46"/>
<circle cx="400" cy="40.6" r=".46"/>
<circle cx="400" cy="30.5" r=".46"/>
<circle cx="400" cy="33" r=".46"/>
<circle cx="400" cy="35.6" r=".46"/>
<circle cx="400" cy="43.2" r=".46"/>
<circle cx="400" cy="45.7" r=".46"/>
<circle cx="344.2" cy="194.3" r=".46"/>
<circle cx="344.2" cy="209.6" r=".46"/>
<circle cx="344.2" cy="217.2" r=".46"/>
<circle cx="344.2" cy="212.1" r=".46"/>
<circle cx="344.2" cy="214.6" r=".46"/>
<circle cx="344.2" cy="207" r=".46"/>
<circle cx="344.2" cy="199.4" r=".46"/>
<circle cx="400" cy="61" r=".46"/>
<circle cx="400" cy="63.5" r=".46"/>
<circle cx="400" cy="50.8" r=".46"/>
<circle cx="400" cy="53.3" r=".46"/>
<circle cx="400" cy="58.4" r=".46"/>
<circle cx="400" cy="55.9" r=".46"/>
<circle cx="400" cy="66" r=".46"/>
<circle cx="400" cy="68.6" r=".46"/>
<circle cx="400" cy="48.3" r=".46"/>
<circle cx="109.2" cy="22.9" r=".46"/>
<circle cx="118.1" cy="22.9" r=".46"/>
<circle cx="177.8" cy="22.9" r=".46"/>
<circle cx="134.6" cy="22.9" r=".46"/>
<circle cx="127" cy="22.9" r=".46"/>
<circle cx="195.6" cy="22.9" r=".46"/>
<circle cx="186.7" cy="22.9" r=".46"/>
<circle cx="204.5" cy="22.9" r=".46"/>
<circle cx="143.5" cy="22.9" r=".46"/>
<circle cx="152.4" cy="22.9" r=".46"/>
<circle cx="170.2" cy="22.9" r=".46"/>
<circle cx="161.3" cy="22.9" r=".46"/>
<circle cx="400" cy="22.9" r=".46"/>
<circle cx="400" cy="25.4" r=".46"/>
<circle cx="344.2" cy="204.5" r=".46"/>
<circle cx="344.2" cy="196.9" r=".46"/>
<circle cx="344.2" cy="201.9" r=".46"/>
<circle cx="344.2" cy="191.8" r=".46"/>
<circle cx="400" cy="189.2" r=".46"/>
<circle cx="400" cy="191.8" r=".46"/>
<circle cx="344.2" cy="189.2" r=".46"/>
<circle cx="400" cy="214.6" r=".46"/>
<circle cx="344.2" cy="224.8" r=".46"/>
<circle cx="344.2" cy="227.3" r=".46"/>
<circle cx="344.2" cy="237.5" r=".46"/>
<circle cx="344.2" cy="240" r=".46"/>
<circle cx="344.2" cy="232.4" r=".46"/>
<circle cx="344.2" cy="229.9" r=".46"/>
<circle cx="344.2" cy="234.9" r=".46"/>
<circle cx="400" cy="219.7" r=".46"/>
<circle cx="400" cy="217.2" r=".46"/>
<circle cx="400" cy="237.5" r=".46"/>
<circle cx="400" cy="240" r=".46"/>
<circle cx="400" cy="224.8" r=".46"/>
<circle cx="400" cy="222.2" r=".46"/>
<circle cx="400" cy="232.4" r=".46"/>
<circle cx="400" cy="227.3" r=".46"/>
<circle cx="400" cy="229.9" r=".46"/>
<circle cx="400" cy="234.9" r=".46"/>
<circle cx="344.2" cy="222.2" r=".46"/>
<circle cx="344.2" cy="219.7" r=".46"/>
<circle cx="400" cy="209.6" r=".46"/>
<circle cx="400" cy="212.1" r=".46"/>
<circle cx="400" cy="207" r=".46"/>
<circle cx="400" cy="204.5" r=".46"/>
<circle cx="400" cy="194.3" r=".46"/>
<circle cx="400" cy="196.9" r=".46"/>
<circle cx="400" cy="201.9" r=".46"/>
<circle cx="400" cy="199.4" r=".46"/>
</g>
<use href="#words"/>
</svg>
